VERSION 5.7 ;
BUSBITCHARS "[]" ;
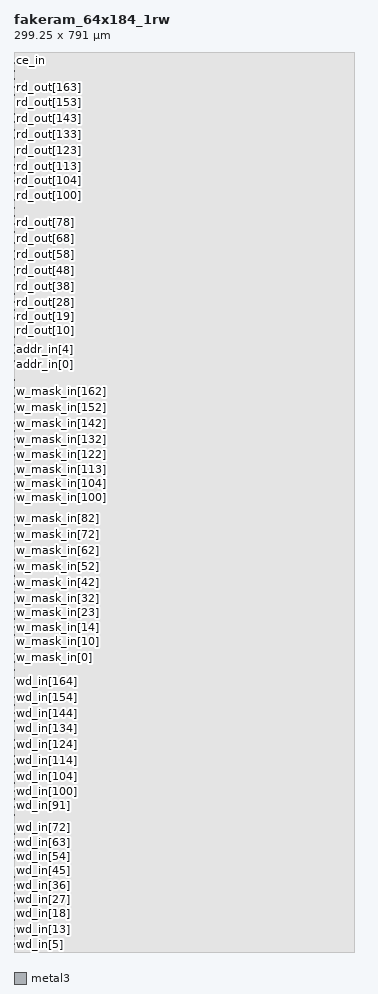
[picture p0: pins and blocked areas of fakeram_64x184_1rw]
MACRO fakeram_64x184_1rw
  FOREIGN fakeram_64x184_1rw 0 0 ;
  SYMMETRY X Y R90 ;
  SIZE 299.250 BY 791.000 ;
  CLASS BLOCK ;
  PIN wd_in[0]
    DIRECTION INPUT ;
    USE SIGNAL ;
    SHAPE ABUTMENT ;
    PORT
      LAYER metal3 ;
      RECT 0.000 1.400 0.140 1.540 ;
    END
  END wd_in[0]
  PIN wd_in[1]
    DIRECTION INPUT ;
    USE SIGNAL ;
    SHAPE ABUTMENT ;
    PORT
      LAYER metal3 ;
      RECT 0.000 2.800 0.140 2.940 ;
    END
  END wd_in[1]
  PIN wd_in[2]
    DIRECTION INPUT ;
    USE SIGNAL ;
    SHAPE ABUTMENT ;
    PORT
      LAYER metal3 ;
      RECT 0.000 4.200 0.140 4.340 ;
    END
  END wd_in[2]
  PIN wd_in[3]
    DIRECTION INPUT ;
    USE SIGNAL ;
    SHAPE ABUTMENT ;
    PORT
      LAYER metal3 ;
      RECT 0.000 5.600 0.140 5.740 ;
    END
  END wd_in[3]
  PIN wd_in[4]
    DIRECTION INPUT ;
    USE SIGNAL ;
    SHAPE ABUTMENT ;
    PORT
      LAYER metal3 ;
      RECT 0.000 7.000 0.140 7.140 ;
    END
  END wd_in[4]
  PIN wd_in[5]
    DIRECTION INPUT ;
    USE SIGNAL ;
    SHAPE ABUTMENT ;
    PORT
      LAYER metal3 ;
      RECT 0.000 8.400 0.140 8.540 ;
    END
  END wd_in[5]
  PIN wd_in[6]
    DIRECTION INPUT ;
    USE SIGNAL ;
    SHAPE ABUTMENT ;
    PORT
      LAYER metal3 ;
      RECT 0.000 9.800 0.140 9.940 ;
    END
  END wd_in[6]
  PIN wd_in[7]
    DIRECTION INPUT ;
    USE SIGNAL ;
    SHAPE ABUTMENT ;
    PORT
      LAYER metal3 ;
      RECT 0.000 11.200 0.140 11.340 ;
    END
  END wd_in[7]
  PIN wd_in[8]
    DIRECTION INPUT ;
    USE SIGNAL ;
    SHAPE ABUTMENT ;
    PORT
      LAYER metal3 ;
      RECT 0.000 12.600 0.140 12.740 ;
    END
  END wd_in[8]
  PIN wd_in[9]
    DIRECTION INPUT ;
    USE SIGNAL ;
    SHAPE ABUTMENT ;
    PORT
      LAYER metal3 ;
      RECT 0.000 14.000 0.140 14.140 ;
    END
  END wd_in[9]
  PIN wd_in[10]
    DIRECTION INPUT ;
    USE SIGNAL ;
    SHAPE ABUTMENT ;
    PORT
      LAYER metal3 ;
      RECT 0.000 15.400 0.140 15.540 ;
    END
  END wd_in[10]
  PIN wd_in[11]
    DIRECTION INPUT ;
    USE SIGNAL ;
    SHAPE ABUTMENT ;
    PORT
      LAYER metal3 ;
      RECT 0.000 16.800 0.140 16.940 ;
    END
  END wd_in[11]
  PIN wd_in[12]
    DIRECTION INPUT ;
    USE SIGNAL ;
    SHAPE ABUTMENT ;
    PORT
      LAYER metal3 ;
      RECT 0.000 18.200 0.140 18.340 ;
    END
  END wd_in[12]
  PIN wd_in[13]
    DIRECTION INPUT ;
    USE SIGNAL ;
    SHAPE ABUTMENT ;
    PORT
      LAYER metal3 ;
      RECT 0.000 19.600 0.140 19.740 ;
    END
  END wd_in[13]
  PIN wd_in[14]
    DIRECTION INPUT ;
    USE SIGNAL ;
    SHAPE ABUTMENT ;
    PORT
      LAYER metal3 ;
      RECT 0.000 21.000 0.140 21.140 ;
    END
  END wd_in[14]
  PIN wd_in[15]
    DIRECTION INPUT ;
    USE SIGNAL ;
    SHAPE ABUTMENT ;
    PORT
      LAYER metal3 ;
      RECT 0.000 22.400 0.140 22.540 ;
    END
  END wd_in[15]
  PIN wd_in[16]
    DIRECTION INPUT ;
    USE SIGNAL ;
    SHAPE ABUTMENT ;
    PORT
      LAYER metal3 ;
      RECT 0.000 23.800 0.140 23.940 ;
    END
  END wd_in[16]
  PIN wd_in[17]
    DIRECTION INPUT ;
    USE SIGNAL ;
    SHAPE ABUTMENT ;
    PORT
      LAYER metal3 ;
      RECT 0.000 25.200 0.140 25.340 ;
    END
  END wd_in[17]
  PIN wd_in[18]
    DIRECTION INPUT ;
    USE SIGNAL ;
    SHAPE ABUTMENT ;
    PORT
      LAYER metal3 ;
      RECT 0.000 26.600 0.140 26.740 ;
    END
  END wd_in[18]
  PIN wd_in[19]
    DIRECTION INPUT ;
    USE SIGNAL ;
    SHAPE ABUTMENT ;
    PORT
      LAYER metal3 ;
      RECT 0.000 28.000 0.140 28.140 ;
    END
  END wd_in[19]
  PIN wd_in[20]
    DIRECTION INPUT ;
    USE SIGNAL ;
    SHAPE ABUTMENT ;
    PORT
      LAYER metal3 ;
      RECT 0.000 29.400 0.140 29.540 ;
    END
  END wd_in[20]
  PIN wd_in[21]
    DIRECTION INPUT ;
    USE SIGNAL ;
    SHAPE ABUTMENT ;
    PORT
      LAYER metal3 ;
      RECT 0.000 30.800 0.140 30.940 ;
    END
  END wd_in[21]
  PIN wd_in[22]
    DIRECTION INPUT ;
    USE SIGNAL ;
    SHAPE ABUTMENT ;
    PORT
      LAYER metal3 ;
      RECT 0.000 32.200 0.140 32.340 ;
    END
  END wd_in[22]
  PIN wd_in[23]
    DIRECTION INPUT ;
    USE SIGNAL ;
    SHAPE ABUTMENT ;
    PORT
      LAYER metal3 ;
      RECT 0.000 33.600 0.140 33.740 ;
    END
  END wd_in[23]
  PIN wd_in[24]
    DIRECTION INPUT ;
    USE SIGNAL ;
    SHAPE ABUTMENT ;
    PORT
      LAYER metal3 ;
      RECT 0.000 35.000 0.140 35.140 ;
    END
  END wd_in[24]
  PIN wd_in[25]
    DIRECTION INPUT ;
    USE SIGNAL ;
    SHAPE ABUTMENT ;
    PORT
      LAYER metal3 ;
      RECT 0.000 36.400 0.140 36.540 ;
    END
  END wd_in[25]
  PIN wd_in[26]
    DIRECTION INPUT ;
    USE SIGNAL ;
    SHAPE ABUTMENT ;
    PORT
      LAYER metal3 ;
      RECT 0.000 37.800 0.140 37.940 ;
    END
  END wd_in[26]
  PIN wd_in[27]
    DIRECTION INPUT ;
    USE SIGNAL ;
    SHAPE ABUTMENT ;
    PORT
      LAYER metal3 ;
      RECT 0.000 39.200 0.140 39.340 ;
    END
  END wd_in[27]
  PIN wd_in[28]
    DIRECTION INPUT ;
    USE SIGNAL ;
    SHAPE ABUTMENT ;
    PORT
      LAYER metal3 ;
      RECT 0.000 40.600 0.140 40.740 ;
    END
  END wd_in[28]
  PIN wd_in[29]
    DIRECTION INPUT ;
    USE SIGNAL ;
    SHAPE ABUTMENT ;
    PORT
      LAYER metal3 ;
      RECT 0.000 42.000 0.140 42.140 ;
    END
  END wd_in[29]
  PIN wd_in[30]
    DIRECTION INPUT ;
    USE SIGNAL ;
    SHAPE ABUTMENT ;
    PORT
      LAYER metal3 ;
      RECT 0.000 43.400 0.140 43.540 ;
    END
  END wd_in[30]
  PIN wd_in[31]
    DIRECTION INPUT ;
    USE SIGNAL ;
    SHAPE ABUTMENT ;
    PORT
      LAYER metal3 ;
      RECT 0.000 44.800 0.140 44.940 ;
    END
  END wd_in[31]
  PIN wd_in[32]
    DIRECTION INPUT ;
    USE SIGNAL ;
    SHAPE ABUTMENT ;
    PORT
      LAYER metal3 ;
      RECT 0.000 46.200 0.140 46.340 ;
    END
  END wd_in[32]
  PIN wd_in[33]
    DIRECTION INPUT ;
    USE SIGNAL ;
    SHAPE ABUTMENT ;
    PORT
      LAYER metal3 ;
      RECT 0.000 47.600 0.140 47.740 ;
    END
  END wd_in[33]
  PIN wd_in[34]
    DIRECTION INPUT ;
    USE SIGNAL ;
    SHAPE ABUTMENT ;
    PORT
      LAYER metal3 ;
      RECT 0.000 49.000 0.140 49.140 ;
    END
  END wd_in[34]
  PIN wd_in[35]
    DIRECTION INPUT ;
    USE SIGNAL ;
    SHAPE ABUTMENT ;
    PORT
      LAYER metal3 ;
      RECT 0.000 50.400 0.140 50.540 ;
    END
  END wd_in[35]
  PIN wd_in[36]
    DIRECTION INPUT ;
    USE SIGNAL ;
    SHAPE ABUTMENT ;
    PORT
      LAYER metal3 ;
      RECT 0.000 51.800 0.140 51.940 ;
    END
  END wd_in[36]
  PIN wd_in[37]
    DIRECTION INPUT ;
    USE SIGNAL ;
    SHAPE ABUTMENT ;
    PORT
      LAYER metal3 ;
      RECT 0.000 53.200 0.140 53.340 ;
    END
  END wd_in[37]
  PIN wd_in[38]
    DIRECTION INPUT ;
    USE SIGNAL ;
    SHAPE ABUTMENT ;
    PORT
      LAYER metal3 ;
      RECT 0.000 54.600 0.140 54.740 ;
    END
  END wd_in[38]
  PIN wd_in[39]
    DIRECTION INPUT ;
    USE SIGNAL ;
    SHAPE ABUTMENT ;
    PORT
      LAYER metal3 ;
      RECT 0.000 56.000 0.140 56.140 ;
    END
  END wd_in[39]
  PIN wd_in[40]
    DIRECTION INPUT ;
    USE SIGNAL ;
    SHAPE ABUTMENT ;
    PORT
      LAYER metal3 ;
      RECT 0.000 57.400 0.140 57.540 ;
    END
  END wd_in[40]
  PIN wd_in[41]
    DIRECTION INPUT ;
    USE SIGNAL ;
    SHAPE ABUTMENT ;
    PORT
      LAYER metal3 ;
      RECT 0.000 58.800 0.140 58.940 ;
    END
  END wd_in[41]
  PIN wd_in[42]
    DIRECTION INPUT ;
    USE SIGNAL ;
    SHAPE ABUTMENT ;
    PORT
      LAYER metal3 ;
      RECT 0.000 60.200 0.140 60.340 ;
    END
  END wd_in[42]
  PIN wd_in[43]
    DIRECTION INPUT ;
    USE SIGNAL ;
    SHAPE ABUTMENT ;
    PORT
      LAYER metal3 ;
      RECT 0.000 61.600 0.140 61.740 ;
    END
  END wd_in[43]
  PIN wd_in[44]
    DIRECTION INPUT ;
    USE SIGNAL ;
    SHAPE ABUTMENT ;
    PORT
      LAYER metal3 ;
      RECT 0.000 63.000 0.140 63.140 ;
    END
  END wd_in[44]
  PIN wd_in[45]
    DIRECTION INPUT ;
    USE SIGNAL ;
    SHAPE ABUTMENT ;
    PORT
      LAYER metal3 ;
      RECT 0.000 64.400 0.140 64.540 ;
    END
  END wd_in[45]
  PIN wd_in[46]
    DIRECTION INPUT ;
    USE SIGNAL ;
    SHAPE ABUTMENT ;
    PORT
      LAYER metal3 ;
      RECT 0.000 65.800 0.140 65.940 ;
    END
  END wd_in[46]
  PIN wd_in[47]
    DIRECTION INPUT ;
    USE SIGNAL ;
    SHAPE ABUTMENT ;
    PORT
      LAYER metal3 ;
      RECT 0.000 67.200 0.140 67.340 ;
    END
  END wd_in[47]
  PIN wd_in[48]
    DIRECTION INPUT ;
    USE SIGNAL ;
    SHAPE ABUTMENT ;
    PORT
      LAYER metal3 ;
      RECT 0.000 68.600 0.140 68.740 ;
    END
  END wd_in[48]
  PIN wd_in[49]
    DIRECTION INPUT ;
    USE SIGNAL ;
    SHAPE ABUTMENT ;
    PORT
      LAYER metal3 ;
      RECT 0.000 70.000 0.140 70.140 ;
    END
  END wd_in[49]
  PIN wd_in[50]
    DIRECTION INPUT ;
    USE SIGNAL ;
    SHAPE ABUTMENT ;
    PORT
      LAYER metal3 ;
      RECT 0.000 71.400 0.140 71.540 ;
    END
  END wd_in[50]
  PIN wd_in[51]
    DIRECTION INPUT ;
    USE SIGNAL ;
    SHAPE ABUTMENT ;
    PORT
      LAYER metal3 ;
      RECT 0.000 72.800 0.140 72.940 ;
    END
  END wd_in[51]
  PIN wd_in[52]
    DIRECTION INPUT ;
    USE SIGNAL ;
    SHAPE ABUTMENT ;
    PORT
      LAYER metal3 ;
      RECT 0.000 74.200 0.140 74.340 ;
    END
  END wd_in[52]
  PIN wd_in[53]
    DIRECTION INPUT ;
    USE SIGNAL ;
    SHAPE ABUTMENT ;
    PORT
      LAYER metal3 ;
      RECT 0.000 75.600 0.140 75.740 ;
    END
  END wd_in[53]
  PIN wd_in[54]
    DIRECTION INPUT ;
    USE SIGNAL ;
    SHAPE ABUTMENT ;
    PORT
      LAYER metal3 ;
      RECT 0.000 77.000 0.140 77.140 ;
    END
  END wd_in[54]
  PIN wd_in[55]
    DIRECTION INPUT ;
    USE SIGNAL ;
    SHAPE ABUTMENT ;
    PORT
      LAYER metal3 ;
      RECT 0.000 78.400 0.140 78.540 ;
    END
  END wd_in[55]
  PIN wd_in[56]
    DIRECTION INPUT ;
    USE SIGNAL ;
    SHAPE ABUTMENT ;
    PORT
      LAYER metal3 ;
      RECT 0.000 79.800 0.140 79.940 ;
    END
  END wd_in[56]
  PIN wd_in[57]
    DIRECTION INPUT ;
    USE SIGNAL ;
    SHAPE ABUTMENT ;
    PORT
      LAYER metal3 ;
      RECT 0.000 81.200 0.140 81.340 ;
    END
  END wd_in[57]
  PIN wd_in[58]
    DIRECTION INPUT ;
    USE SIGNAL ;
    SHAPE ABUTMENT ;
    PORT
      LAYER metal3 ;
      RECT 0.000 82.600 0.140 82.740 ;
    END
  END wd_in[58]
  PIN wd_in[59]
    DIRECTION INPUT ;
    USE SIGNAL ;
    SHAPE ABUTMENT ;
    PORT
      LAYER metal3 ;
      RECT 0.000 84.000 0.140 84.140 ;
    END
  END wd_in[59]
  PIN wd_in[60]
    DIRECTION INPUT ;
    USE SIGNAL ;
    SHAPE ABUTMENT ;
    PORT
      LAYER metal3 ;
      RECT 0.000 85.400 0.140 85.540 ;
    END
  END wd_in[60]
  PIN wd_in[61]
    DIRECTION INPUT ;
    USE SIGNAL ;
    SHAPE ABUTMENT ;
    PORT
      LAYER metal3 ;
      RECT 0.000 86.800 0.140 86.940 ;
    END
  END wd_in[61]
  PIN wd_in[62]
    DIRECTION INPUT ;
    USE SIGNAL ;
    SHAPE ABUTMENT ;
    PORT
      LAYER metal3 ;
      RECT 0.000 88.200 0.140 88.340 ;
    END
  END wd_in[62]
  PIN wd_in[63]
    DIRECTION INPUT ;
    USE SIGNAL ;
    SHAPE ABUTMENT ;
    PORT
      LAYER metal3 ;
      RECT 0.000 89.600 0.140 89.740 ;
    END
  END wd_in[63]
  PIN wd_in[64]
    DIRECTION INPUT ;
    USE SIGNAL ;
    SHAPE ABUTMENT ;
    PORT
      LAYER metal3 ;
      RECT 0.000 91.000 0.140 91.140 ;
    END
  END wd_in[64]
  PIN wd_in[65]
    DIRECTION INPUT ;
    USE SIGNAL ;
    SHAPE ABUTMENT ;
    PORT
      LAYER metal3 ;
      RECT 0.000 92.400 0.140 92.540 ;
    END
  END wd_in[65]
  PIN wd_in[66]
    DIRECTION INPUT ;
    USE SIGNAL ;
    SHAPE ABUTMENT ;
    PORT
      LAYER metal3 ;
      RECT 0.000 93.800 0.140 93.940 ;
    END
  END wd_in[66]
  PIN wd_in[67]
    DIRECTION INPUT ;
    USE SIGNAL ;
    SHAPE ABUTMENT ;
    PORT
      LAYER metal3 ;
      RECT 0.000 95.200 0.140 95.340 ;
    END
  END wd_in[67]
  PIN wd_in[68]
    DIRECTION INPUT ;
    USE SIGNAL ;
    SHAPE ABUTMENT ;
    PORT
      LAYER metal3 ;
      RECT 0.000 96.600 0.140 96.740 ;
    END
  END wd_in[68]
  PIN wd_in[69]
    DIRECTION INPUT ;
    USE SIGNAL ;
    SHAPE ABUTMENT ;
    PORT
      LAYER metal3 ;
      RECT 0.000 98.000 0.140 98.140 ;
    END
  END wd_in[69]
  PIN wd_in[70]
    DIRECTION INPUT ;
    USE SIGNAL ;
    SHAPE ABUTMENT ;
    PORT
      LAYER metal3 ;
      RECT 0.000 99.400 0.140 99.540 ;
    END
  END wd_in[70]
  PIN wd_in[71]
    DIRECTION INPUT ;
    USE SIGNAL ;
    SHAPE ABUTMENT ;
    PORT
      LAYER metal3 ;
      RECT 0.000 100.800 0.140 100.940 ;
    END
  END wd_in[71]
  PIN wd_in[72]
    DIRECTION INPUT ;
    USE SIGNAL ;
    SHAPE ABUTMENT ;
    PORT
      LAYER metal3 ;
      RECT 0.000 102.200 0.140 102.340 ;
    END
  END wd_in[72]
  PIN wd_in[73]
    DIRECTION INPUT ;
    USE SIGNAL ;
    SHAPE ABUTMENT ;
    PORT
      LAYER metal3 ;
      RECT 0.000 103.600 0.140 103.740 ;
    END
  END wd_in[73]
  PIN wd_in[74]
    DIRECTION INPUT ;
    USE SIGNAL ;
    SHAPE ABUTMENT ;
    PORT
      LAYER metal3 ;
      RECT 0.000 105.000 0.140 105.140 ;
    END
  END wd_in[74]
  PIN wd_in[75]
    DIRECTION INPUT ;
    USE SIGNAL ;
    SHAPE ABUTMENT ;
    PORT
      LAYER metal3 ;
      RECT 0.000 106.400 0.140 106.540 ;
    END
  END wd_in[75]
  PIN wd_in[76]
    DIRECTION INPUT ;
    USE SIGNAL ;
    SHAPE ABUTMENT ;
    PORT
      LAYER metal3 ;
      RECT 0.000 107.800 0.140 107.940 ;
    END
  END wd_in[76]
  PIN wd_in[77]
    DIRECTION INPUT ;
    USE SIGNAL ;
    SHAPE ABUTMENT ;
    PORT
      LAYER metal3 ;
      RECT 0.000 109.200 0.140 109.340 ;
    END
  END wd_in[77]
  PIN wd_in[78]
    DIRECTION INPUT ;
    USE SIGNAL ;
    SHAPE ABUTMENT ;
    PORT
      LAYER metal3 ;
      RECT 0.000 110.600 0.140 110.740 ;
    END
  END wd_in[78]
  PIN wd_in[79]
    DIRECTION INPUT ;
    USE SIGNAL ;
    SHAPE ABUTMENT ;
    PORT
      LAYER metal3 ;
      RECT 0.000 112.000 0.140 112.140 ;
    END
  END wd_in[79]
  PIN wd_in[80]
    DIRECTION INPUT ;
    USE SIGNAL ;
    SHAPE ABUTMENT ;
    PORT
      LAYER metal3 ;
      RECT 0.000 113.400 0.140 113.540 ;
    END
  END wd_in[80]
  PIN wd_in[81]
    DIRECTION INPUT ;
    USE SIGNAL ;
    SHAPE ABUTMENT ;
    PORT
      LAYER metal3 ;
      RECT 0.000 114.800 0.140 114.940 ;
    END
  END wd_in[81]
  PIN wd_in[82]
    DIRECTION INPUT ;
    USE SIGNAL ;
    SHAPE ABUTMENT ;
    PORT
      LAYER metal3 ;
      RECT 0.000 116.200 0.140 116.340 ;
    END
  END wd_in[82]
  PIN wd_in[83]
    DIRECTION INPUT ;
    USE SIGNAL ;
    SHAPE ABUTMENT ;
    PORT
      LAYER metal3 ;
      RECT 0.000 117.600 0.140 117.740 ;
    END
  END wd_in[83]
  PIN wd_in[84]
    DIRECTION INPUT ;
    USE SIGNAL ;
    SHAPE ABUTMENT ;
    PORT
      LAYER metal3 ;
      RECT 0.000 119.000 0.140 119.140 ;
    END
  END wd_in[84]
  PIN wd_in[85]
    DIRECTION INPUT ;
    USE SIGNAL ;
    SHAPE ABUTMENT ;
    PORT
      LAYER metal3 ;
      RECT 0.000 120.400 0.140 120.540 ;
    END
  END wd_in[85]
  PIN wd_in[86]
    DIRECTION INPUT ;
    USE SIGNAL ;
    SHAPE ABUTMENT ;
    PORT
      LAYER metal3 ;
      RECT 0.000 121.800 0.140 121.940 ;
    END
  END wd_in[86]
  PIN wd_in[87]
    DIRECTION INPUT ;
    USE SIGNAL ;
    SHAPE ABUTMENT ;
    PORT
      LAYER metal3 ;
      RECT 0.000 123.200 0.140 123.340 ;
    END
  END wd_in[87]
  PIN wd_in[88]
    DIRECTION INPUT ;
    USE SIGNAL ;
    SHAPE ABUTMENT ;
    PORT
      LAYER metal3 ;
      RECT 0.000 124.600 0.140 124.740 ;
    END
  END wd_in[88]
  PIN wd_in[89]
    DIRECTION INPUT ;
    USE SIGNAL ;
    SHAPE ABUTMENT ;
    PORT
      LAYER metal3 ;
      RECT 0.000 126.000 0.140 126.140 ;
    END
  END wd_in[89]
  PIN wd_in[90]
    DIRECTION INPUT ;
    USE SIGNAL ;
    SHAPE ABUTMENT ;
    PORT
      LAYER metal3 ;
      RECT 0.000 127.400 0.140 127.540 ;
    END
  END wd_in[90]
  PIN wd_in[91]
    DIRECTION INPUT ;
    USE SIGNAL ;
    SHAPE ABUTMENT ;
    PORT
      LAYER metal3 ;
      RECT 0.000 128.800 0.140 128.940 ;
    END
  END wd_in[91]
  PIN wd_in[92]
    DIRECTION INPUT ;
    USE SIGNAL ;
    SHAPE ABUTMENT ;
    PORT
      LAYER metal3 ;
      RECT 0.000 130.200 0.140 130.340 ;
    END
  END wd_in[92]
  PIN wd_in[93]
    DIRECTION INPUT ;
    USE SIGNAL ;
    SHAPE ABUTMENT ;
    PORT
      LAYER metal3 ;
      RECT 0.000 131.600 0.140 131.740 ;
    END
  END wd_in[93]
  PIN wd_in[94]
    DIRECTION INPUT ;
    USE SIGNAL ;
    SHAPE ABUTMENT ;
    PORT
      LAYER metal3 ;
      RECT 0.000 133.000 0.140 133.140 ;
    END
  END wd_in[94]
  PIN wd_in[95]
    DIRECTION INPUT ;
    USE SIGNAL ;
    SHAPE ABUTMENT ;
    PORT
      LAYER metal3 ;
      RECT 0.000 134.400 0.140 134.540 ;
    END
  END wd_in[95]
  PIN wd_in[96]
    DIRECTION INPUT ;
    USE SIGNAL ;
    SHAPE ABUTMENT ;
    PORT
      LAYER metal3 ;
      RECT 0.000 135.800 0.140 135.940 ;
    END
  END wd_in[96]
  PIN wd_in[97]
    DIRECTION INPUT ;
    USE SIGNAL ;
    SHAPE ABUTMENT ;
    PORT
      LAYER metal3 ;
      RECT 0.000 137.200 0.140 137.340 ;
    END
  END wd_in[97]
  PIN wd_in[98]
    DIRECTION INPUT ;
    USE SIGNAL ;
    SHAPE ABUTMENT ;
    PORT
      LAYER metal3 ;
      RECT 0.000 138.600 0.140 138.740 ;
    END
  END wd_in[98]
  PIN wd_in[99]
    DIRECTION INPUT ;
    USE SIGNAL ;
    SHAPE ABUTMENT ;
    PORT
      LAYER metal3 ;
      RECT 0.000 140.000 0.140 140.140 ;
    END
  END wd_in[99]
  PIN wd_in[100]
    DIRECTION INPUT ;
    USE SIGNAL ;
    SHAPE ABUTMENT ;
    PORT
      LAYER metal3 ;
      RECT 0.000 141.400 0.140 141.540 ;
    END
  END wd_in[100]
  PIN wd_in[101]
    DIRECTION INPUT ;
    USE SIGNAL ;
    SHAPE ABUTMENT ;
    PORT
      LAYER metal3 ;
      RECT 0.000 142.800 0.140 142.940 ;
    END
  END wd_in[101]
  PIN wd_in[102]
    DIRECTION INPUT ;
    USE SIGNAL ;
    SHAPE ABUTMENT ;
    PORT
      LAYER metal3 ;
      RECT 0.000 144.200 0.140 144.340 ;
    END
  END wd_in[102]
  PIN wd_in[103]
    DIRECTION INPUT ;
    USE SIGNAL ;
    SHAPE ABUTMENT ;
    PORT
      LAYER metal3 ;
      RECT 0.000 145.600 0.140 145.740 ;
    END
  END wd_in[103]
  PIN wd_in[104]
    DIRECTION INPUT ;
    USE SIGNAL ;
    SHAPE ABUTMENT ;
    PORT
      LAYER metal3 ;
      RECT 0.000 147.000 0.140 147.140 ;
    END
  END wd_in[104]
  PIN wd_in[105]
    DIRECTION INPUT ;
    USE SIGNAL ;
    SHAPE ABUTMENT ;
    PORT
      LAYER metal3 ;
      RECT 0.000 148.400 0.140 148.540 ;
    END
  END wd_in[105]
  PIN wd_in[106]
    DIRECTION INPUT ;
    USE SIGNAL ;
    SHAPE ABUTMENT ;
    PORT
      LAYER metal3 ;
      RECT 0.000 149.800 0.140 149.940 ;
    END
  END wd_in[106]
  PIN wd_in[107]
    DIRECTION INPUT ;
    USE SIGNAL ;
    SHAPE ABUTMENT ;
    PORT
      LAYER metal3 ;
      RECT 0.000 151.200 0.140 151.340 ;
    END
  END wd_in[107]
  PIN wd_in[108]
    DIRECTION INPUT ;
    USE SIGNAL ;
    SHAPE ABUTMENT ;
    PORT
      LAYER metal3 ;
      RECT 0.000 152.600 0.140 152.740 ;
    END
  END wd_in[108]
  PIN wd_in[109]
    DIRECTION INPUT ;
    USE SIGNAL ;
    SHAPE ABUTMENT ;
    PORT
      LAYER metal3 ;
      RECT 0.000 154.000 0.140 154.140 ;
    END
  END wd_in[109]
  PIN wd_in[110]
    DIRECTION INPUT ;
    USE SIGNAL ;
    SHAPE ABUTMENT ;
    PORT
      LAYER metal3 ;
      RECT 0.000 155.400 0.140 155.540 ;
    END
  END wd_in[110]
  PIN wd_in[111]
    DIRECTION INPUT ;
    USE SIGNAL ;
    SHAPE ABUTMENT ;
    PORT
      LAYER metal3 ;
      RECT 0.000 156.800 0.140 156.940 ;
    END
  END wd_in[111]
  PIN wd_in[112]
    DIRECTION INPUT ;
    USE SIGNAL ;
    SHAPE ABUTMENT ;
    PORT
      LAYER metal3 ;
      RECT 0.000 158.200 0.140 158.340 ;
    END
  END wd_in[112]
  PIN wd_in[113]
    DIRECTION INPUT ;
    USE SIGNAL ;
    SHAPE ABUTMENT ;
    PORT
      LAYER metal3 ;
      RECT 0.000 159.600 0.140 159.740 ;
    END
  END wd_in[113]
  PIN wd_in[114]
    DIRECTION INPUT ;
    USE SIGNAL ;
    SHAPE ABUTMENT ;
    PORT
      LAYER metal3 ;
      RECT 0.000 161.000 0.140 161.140 ;
    END
  END wd_in[114]
  PIN wd_in[115]
    DIRECTION INPUT ;
    USE SIGNAL ;
    SHAPE ABUTMENT ;
    PORT
      LAYER metal3 ;
      RECT 0.000 162.400 0.140 162.540 ;
    END
  END wd_in[115]
  PIN wd_in[116]
    DIRECTION INPUT ;
    USE SIGNAL ;
    SHAPE ABUTMENT ;
    PORT
      LAYER metal3 ;
      RECT 0.000 163.800 0.140 163.940 ;
    END
  END wd_in[116]
  PIN wd_in[117]
    DIRECTION INPUT ;
    USE SIGNAL ;
    SHAPE ABUTMENT ;
    PORT
      LAYER metal3 ;
      RECT 0.000 165.200 0.140 165.340 ;
    END
  END wd_in[117]
  PIN wd_in[118]
    DIRECTION INPUT ;
    USE SIGNAL ;
    SHAPE ABUTMENT ;
    PORT
      LAYER metal3 ;
      RECT 0.000 166.600 0.140 166.740 ;
    END
  END wd_in[118]
  PIN wd_in[119]
    DIRECTION INPUT ;
    USE SIGNAL ;
    SHAPE ABUTMENT ;
    PORT
      LAYER metal3 ;
      RECT 0.000 168.000 0.140 168.140 ;
    END
  END wd_in[119]
  PIN wd_in[120]
    DIRECTION INPUT ;
    USE SIGNAL ;
    SHAPE ABUTMENT ;
    PORT
      LAYER metal3 ;
      RECT 0.000 169.400 0.140 169.540 ;
    END
  END wd_in[120]
  PIN wd_in[121]
    DIRECTION INPUT ;
    USE SIGNAL ;
    SHAPE ABUTMENT ;
    PORT
      LAYER metal3 ;
      RECT 0.000 170.800 0.140 170.940 ;
    END
  END wd_in[121]
  PIN wd_in[122]
    DIRECTION INPUT ;
    USE SIGNAL ;
    SHAPE ABUTMENT ;
    PORT
      LAYER metal3 ;
      RECT 0.000 172.200 0.140 172.340 ;
    END
  END wd_in[122]
  PIN wd_in[123]
    DIRECTION INPUT ;
    USE SIGNAL ;
    SHAPE ABUTMENT ;
    PORT
      LAYER metal3 ;
      RECT 0.000 173.600 0.140 173.740 ;
    END
  END wd_in[123]
  PIN wd_in[124]
    DIRECTION INPUT ;
    USE SIGNAL ;
    SHAPE ABUTMENT ;
    PORT
      LAYER metal3 ;
      RECT 0.000 175.000 0.140 175.140 ;
    END
  END wd_in[124]
  PIN wd_in[125]
    DIRECTION INPUT ;
    USE SIGNAL ;
    SHAPE ABUTMENT ;
    PORT
      LAYER metal3 ;
      RECT 0.000 176.400 0.140 176.540 ;
    END
  END wd_in[125]
  PIN wd_in[126]
    DIRECTION INPUT ;
    USE SIGNAL ;
    SHAPE ABUTMENT ;
    PORT
      LAYER metal3 ;
      RECT 0.000 177.800 0.140 177.940 ;
    END
  END wd_in[126]
  PIN wd_in[127]
    DIRECTION INPUT ;
    USE SIGNAL ;
    SHAPE ABUTMENT ;
    PORT
      LAYER metal3 ;
      RECT 0.000 179.200 0.140 179.340 ;
    END
  END wd_in[127]
  PIN wd_in[128]
    DIRECTION INPUT ;
    USE SIGNAL ;
    SHAPE ABUTMENT ;
    PORT
      LAYER metal3 ;
      RECT 0.000 180.600 0.140 180.740 ;
    END
  END wd_in[128]
  PIN wd_in[129]
    DIRECTION INPUT ;
    USE SIGNAL ;
    SHAPE ABUTMENT ;
    PORT
      LAYER metal3 ;
      RECT 0.000 182.000 0.140 182.140 ;
    END
  END wd_in[129]
  PIN wd_in[130]
    DIRECTION INPUT ;
    USE SIGNAL ;
    SHAPE ABUTMENT ;
    PORT
      LAYER metal3 ;
      RECT 0.000 183.400 0.140 183.540 ;
    END
  END wd_in[130]
  PIN wd_in[131]
    DIRECTION INPUT ;
    USE SIGNAL ;
    SHAPE ABUTMENT ;
    PORT
      LAYER metal3 ;
      RECT 0.000 184.800 0.140 184.940 ;
    END
  END wd_in[131]
  PIN wd_in[132]
    DIRECTION INPUT ;
    USE SIGNAL ;
    SHAPE ABUTMENT ;
    PORT
      LAYER metal3 ;
      RECT 0.000 186.200 0.140 186.340 ;
    END
  END wd_in[132]
  PIN wd_in[133]
    DIRECTION INPUT ;
    USE SIGNAL ;
    SHAPE ABUTMENT ;
    PORT
      LAYER metal3 ;
      RECT 0.000 187.600 0.140 187.740 ;
    END
  END wd_in[133]
  PIN wd_in[134]
    DIRECTION INPUT ;
    USE SIGNAL ;
    SHAPE ABUTMENT ;
    PORT
      LAYER metal3 ;
      RECT 0.000 189.000 0.140 189.140 ;
    END
  END wd_in[134]
  PIN wd_in[135]
    DIRECTION INPUT ;
    USE SIGNAL ;
    SHAPE ABUTMENT ;
    PORT
      LAYER metal3 ;
      RECT 0.000 190.400 0.140 190.540 ;
    END
  END wd_in[135]
  PIN wd_in[136]
    DIRECTION INPUT ;
    USE SIGNAL ;
    SHAPE ABUTMENT ;
    PORT
      LAYER metal3 ;
      RECT 0.000 191.800 0.140 191.940 ;
    END
  END wd_in[136]
  PIN wd_in[137]
    DIRECTION INPUT ;
    USE SIGNAL ;
    SHAPE ABUTMENT ;
    PORT
      LAYER metal3 ;
      RECT 0.000 193.200 0.140 193.340 ;
    END
  END wd_in[137]
  PIN wd_in[138]
    DIRECTION INPUT ;
    USE SIGNAL ;
    SHAPE ABUTMENT ;
    PORT
      LAYER metal3 ;
      RECT 0.000 194.600 0.140 194.740 ;
    END
  END wd_in[138]
  PIN wd_in[139]
    DIRECTION INPUT ;
    USE SIGNAL ;
    SHAPE ABUTMENT ;
    PORT
      LAYER metal3 ;
      RECT 0.000 196.000 0.140 196.140 ;
    END
  END wd_in[139]
  PIN wd_in[140]
    DIRECTION INPUT ;
    USE SIGNAL ;
    SHAPE ABUTMENT ;
    PORT
      LAYER metal3 ;
      RECT 0.000 197.400 0.140 197.540 ;
    END
  END wd_in[140]
  PIN wd_in[141]
    DIRECTION INPUT ;
    USE SIGNAL ;
    SHAPE ABUTMENT ;
    PORT
      LAYER metal3 ;
      RECT 0.000 198.800 0.140 198.940 ;
    END
  END wd_in[141]
  PIN wd_in[142]
    DIRECTION INPUT ;
    USE SIGNAL ;
    SHAPE ABUTMENT ;
    PORT
      LAYER metal3 ;
      RECT 0.000 200.200 0.140 200.340 ;
    END
  END wd_in[142]
  PIN wd_in[143]
    DIRECTION INPUT ;
    USE SIGNAL ;
    SHAPE ABUTMENT ;
    PORT
      LAYER metal3 ;
      RECT 0.000 201.600 0.140 201.740 ;
    END
  END wd_in[143]
  PIN wd_in[144]
    DIRECTION INPUT ;
    USE SIGNAL ;
    SHAPE ABUTMENT ;
    PORT
      LAYER metal3 ;
      RECT 0.000 203.000 0.140 203.140 ;
    END
  END wd_in[144]
  PIN wd_in[145]
    DIRECTION INPUT ;
    USE SIGNAL ;
    SHAPE ABUTMENT ;
    PORT
      LAYER metal3 ;
      RECT 0.000 204.400 0.140 204.540 ;
    END
  END wd_in[145]
  PIN wd_in[146]
    DIRECTION INPUT ;
    USE SIGNAL ;
    SHAPE ABUTMENT ;
    PORT
      LAYER metal3 ;
      RECT 0.000 205.800 0.140 205.940 ;
    END
  END wd_in[146]
  PIN wd_in[147]
    DIRECTION INPUT ;
    USE SIGNAL ;
    SHAPE ABUTMENT ;
    PORT
      LAYER metal3 ;
      RECT 0.000 207.200 0.140 207.340 ;
    END
  END wd_in[147]
  PIN wd_in[148]
    DIRECTION INPUT ;
    USE SIGNAL ;
    SHAPE ABUTMENT ;
    PORT
      LAYER metal3 ;
      RECT 0.000 208.600 0.140 208.740 ;
    END
  END wd_in[148]
  PIN wd_in[149]
    DIRECTION INPUT ;
    USE SIGNAL ;
    SHAPE ABUTMENT ;
    PORT
      LAYER metal3 ;
      RECT 0.000 210.000 0.140 210.140 ;
    END
  END wd_in[149]
  PIN wd_in[150]
    DIRECTION INPUT ;
    USE SIGNAL ;
    SHAPE ABUTMENT ;
    PORT
      LAYER metal3 ;
      RECT 0.000 211.400 0.140 211.540 ;
    END
  END wd_in[150]
  PIN wd_in[151]
    DIRECTION INPUT ;
    USE SIGNAL ;
    SHAPE ABUTMENT ;
    PORT
      LAYER metal3 ;
      RECT 0.000 212.800 0.140 212.940 ;
    END
  END wd_in[151]
  PIN wd_in[152]
    DIRECTION INPUT ;
    USE SIGNAL ;
    SHAPE ABUTMENT ;
    PORT
      LAYER metal3 ;
      RECT 0.000 214.200 0.140 214.340 ;
    END
  END wd_in[152]
  PIN wd_in[153]
    DIRECTION INPUT ;
    USE SIGNAL ;
    SHAPE ABUTMENT ;
    PORT
      LAYER metal3 ;
      RECT 0.000 215.600 0.140 215.740 ;
    END
  END wd_in[153]
  PIN wd_in[154]
    DIRECTION INPUT ;
    USE SIGNAL ;
    SHAPE ABUTMENT ;
    PORT
      LAYER metal3 ;
      RECT 0.000 217.000 0.140 217.140 ;
    END
  END wd_in[154]
  PIN wd_in[155]
    DIRECTION INPUT ;
    USE SIGNAL ;
    SHAPE ABUTMENT ;
    PORT
      LAYER metal3 ;
      RECT 0.000 218.400 0.140 218.540 ;
    END
  END wd_in[155]
  PIN wd_in[156]
    DIRECTION INPUT ;
    USE SIGNAL ;
    SHAPE ABUTMENT ;
    PORT
      LAYER metal3 ;
      RECT 0.000 219.800 0.140 219.940 ;
    END
  END wd_in[156]
  PIN wd_in[157]
    DIRECTION INPUT ;
    USE SIGNAL ;
    SHAPE ABUTMENT ;
    PORT
      LAYER metal3 ;
      RECT 0.000 221.200 0.140 221.340 ;
    END
  END wd_in[157]
  PIN wd_in[158]
    DIRECTION INPUT ;
    USE SIGNAL ;
    SHAPE ABUTMENT ;
    PORT
      LAYER metal3 ;
      RECT 0.000 222.600 0.140 222.740 ;
    END
  END wd_in[158]
  PIN wd_in[159]
    DIRECTION INPUT ;
    USE SIGNAL ;
    SHAPE ABUTMENT ;
    PORT
      LAYER metal3 ;
      RECT 0.000 224.000 0.140 224.140 ;
    END
  END wd_in[159]
  PIN wd_in[160]
    DIRECTION INPUT ;
    USE SIGNAL ;
    SHAPE ABUTMENT ;
    PORT
      LAYER metal3 ;
      RECT 0.000 225.400 0.140 225.540 ;
    END
  END wd_in[160]
  PIN wd_in[161]
    DIRECTION INPUT ;
    USE SIGNAL ;
    SHAPE ABUTMENT ;
    PORT
      LAYER metal3 ;
      RECT 0.000 226.800 0.140 226.940 ;
    END
  END wd_in[161]
  PIN wd_in[162]
    DIRECTION INPUT ;
    USE SIGNAL ;
    SHAPE ABUTMENT ;
    PORT
      LAYER metal3 ;
      RECT 0.000 228.200 0.140 228.340 ;
    END
  END wd_in[162]
  PIN wd_in[163]
    DIRECTION INPUT ;
    USE SIGNAL ;
    SHAPE ABUTMENT ;
    PORT
      LAYER metal3 ;
      RECT 0.000 229.600 0.140 229.740 ;
    END
  END wd_in[163]
  PIN wd_in[164]
    DIRECTION INPUT ;
    USE SIGNAL ;
    SHAPE ABUTMENT ;
    PORT
      LAYER metal3 ;
      RECT 0.000 231.000 0.140 231.140 ;
    END
  END wd_in[164]
  PIN wd_in[165]
    DIRECTION INPUT ;
    USE SIGNAL ;
    SHAPE ABUTMENT ;
    PORT
      LAYER metal3 ;
      RECT 0.000 232.400 0.140 232.540 ;
    END
  END wd_in[165]
  PIN wd_in[166]
    DIRECTION INPUT ;
    USE SIGNAL ;
    SHAPE ABUTMENT ;
    PORT
      LAYER metal3 ;
      RECT 0.000 233.800 0.140 233.940 ;
    END
  END wd_in[166]
  PIN wd_in[167]
    DIRECTION INPUT ;
    USE SIGNAL ;
    SHAPE ABUTMENT ;
    PORT
      LAYER metal3 ;
      RECT 0.000 235.200 0.140 235.340 ;
    END
  END wd_in[167]
  PIN wd_in[168]
    DIRECTION INPUT ;
    USE SIGNAL ;
    SHAPE ABUTMENT ;
    PORT
      LAYER metal3 ;
      RECT 0.000 236.600 0.140 236.740 ;
    END
  END wd_in[168]
  PIN wd_in[169]
    DIRECTION INPUT ;
    USE SIGNAL ;
    SHAPE ABUTMENT ;
    PORT
      LAYER metal3 ;
      RECT 0.000 238.000 0.140 238.140 ;
    END
  END wd_in[169]
  PIN wd_in[170]
    DIRECTION INPUT ;
    USE SIGNAL ;
    SHAPE ABUTMENT ;
    PORT
      LAYER metal3 ;
      RECT 0.000 239.400 0.140 239.540 ;
    END
  END wd_in[170]
  PIN wd_in[171]
    DIRECTION INPUT ;
    USE SIGNAL ;
    SHAPE ABUTMENT ;
    PORT
      LAYER metal3 ;
      RECT 0.000 240.800 0.140 240.940 ;
    END
  END wd_in[171]
  PIN wd_in[172]
    DIRECTION INPUT ;
    USE SIGNAL ;
    SHAPE ABUTMENT ;
    PORT
      LAYER metal3 ;
      RECT 0.000 242.200 0.140 242.340 ;
    END
  END wd_in[172]
  PIN wd_in[173]
    DIRECTION INPUT ;
    USE SIGNAL ;
    SHAPE ABUTMENT ;
    PORT
      LAYER metal3 ;
      RECT 0.000 243.600 0.140 243.740 ;
    END
  END wd_in[173]
  PIN wd_in[174]
    DIRECTION INPUT ;
    USE SIGNAL ;
    SHAPE ABUTMENT ;
    PORT
      LAYER metal3 ;
      RECT 0.000 245.000 0.140 245.140 ;
    END
  END wd_in[174]
  PIN wd_in[175]
    DIRECTION INPUT ;
    USE SIGNAL ;
    SHAPE ABUTMENT ;
    PORT
      LAYER metal3 ;
      RECT 0.000 246.400 0.140 246.540 ;
    END
  END wd_in[175]
  PIN wd_in[176]
    DIRECTION INPUT ;
    USE SIGNAL ;
    SHAPE ABUTMENT ;
    PORT
      LAYER metal3 ;
      RECT 0.000 247.800 0.140 247.940 ;
    END
  END wd_in[176]
  PIN wd_in[177]
    DIRECTION INPUT ;
    USE SIGNAL ;
    SHAPE ABUTMENT ;
    PORT
      LAYER metal3 ;
      RECT 0.000 249.200 0.140 249.340 ;
    END
  END wd_in[177]
  PIN wd_in[178]
    DIRECTION INPUT ;
    USE SIGNAL ;
    SHAPE ABUTMENT ;
    PORT
      LAYER metal3 ;
      RECT 0.000 250.600 0.140 250.740 ;
    END
  END wd_in[178]
  PIN wd_in[179]
    DIRECTION INPUT ;
    USE SIGNAL ;
    SHAPE ABUTMENT ;
    PORT
      LAYER metal3 ;
      RECT 0.000 252.000 0.140 252.140 ;
    END
  END wd_in[179]
  PIN wd_in[180]
    DIRECTION INPUT ;
    USE SIGNAL ;
    SHAPE ABUTMENT ;
    PORT
      LAYER metal3 ;
      RECT 0.000 253.400 0.140 253.540 ;
    END
  END wd_in[180]
  PIN wd_in[181]
    DIRECTION INPUT ;
    USE SIGNAL ;
    SHAPE ABUTMENT ;
    PORT
      LAYER metal3 ;
      RECT 0.000 254.800 0.140 254.940 ;
    END
  END wd_in[181]
  PIN wd_in[182]
    DIRECTION INPUT ;
    USE SIGNAL ;
    SHAPE ABUTMENT ;
    PORT
      LAYER metal3 ;
      RECT 0.000 256.200 0.140 256.340 ;
    END
  END wd_in[182]
  PIN wd_in[183]
    DIRECTION INPUT ;
    USE SIGNAL ;
    SHAPE ABUTMENT ;
    PORT
      LAYER metal3 ;
      RECT 0.000 257.600 0.140 257.740 ;
    END
  END wd_in[183]
  PIN w_mask_in[0]
    DIRECTION INPUT ;
    USE SIGNAL ;
    SHAPE ABUTMENT ;
    PORT
      LAYER metal3 ;
      RECT 0.000 259.000 0.140 259.140 ;
    END
  END w_mask_in[0]
  PIN w_mask_in[1]
    DIRECTION INPUT ;
    USE SIGNAL ;
    SHAPE ABUTMENT ;
    PORT
      LAYER metal3 ;
      RECT 0.000 260.400 0.140 260.540 ;
    END
  END w_mask_in[1]
  PIN w_mask_in[2]
    DIRECTION INPUT ;
    USE SIGNAL ;
    SHAPE ABUTMENT ;
    PORT
      LAYER metal3 ;
      RECT 0.000 261.800 0.140 261.940 ;
    END
  END w_mask_in[2]
  PIN w_mask_in[3]
    DIRECTION INPUT ;
    USE SIGNAL ;
    SHAPE ABUTMENT ;
    PORT
      LAYER metal3 ;
      RECT 0.000 263.200 0.140 263.340 ;
    END
  END w_mask_in[3]
  PIN w_mask_in[4]
    DIRECTION INPUT ;
    USE SIGNAL ;
    SHAPE ABUTMENT ;
    PORT
      LAYER metal3 ;
      RECT 0.000 264.600 0.140 264.740 ;
    END
  END w_mask_in[4]
  PIN w_mask_in[5]
    DIRECTION INPUT ;
    USE SIGNAL ;
    SHAPE ABUTMENT ;
    PORT
      LAYER metal3 ;
      RECT 0.000 266.000 0.140 266.140 ;
    END
  END w_mask_in[5]
  PIN w_mask_in[6]
    DIRECTION INPUT ;
    USE SIGNAL ;
    SHAPE ABUTMENT ;
    PORT
      LAYER metal3 ;
      RECT 0.000 267.400 0.140 267.540 ;
    END
  END w_mask_in[6]
  PIN w_mask_in[7]
    DIRECTION INPUT ;
    USE SIGNAL ;
    SHAPE ABUTMENT ;
    PORT
      LAYER metal3 ;
      RECT 0.000 268.800 0.140 268.940 ;
    END
  END w_mask_in[7]
  PIN w_mask_in[8]
    DIRECTION INPUT ;
    USE SIGNAL ;
    SHAPE ABUTMENT ;
    PORT
      LAYER metal3 ;
      RECT 0.000 270.200 0.140 270.340 ;
    END
  END w_mask_in[8]
  PIN w_mask_in[9]
    DIRECTION INPUT ;
    USE SIGNAL ;
    SHAPE ABUTMENT ;
    PORT
      LAYER metal3 ;
      RECT 0.000 271.600 0.140 271.740 ;
    END
  END w_mask_in[9]
  PIN w_mask_in[10]
    DIRECTION INPUT ;
    USE SIGNAL ;
    SHAPE ABUTMENT ;
    PORT
      LAYER metal3 ;
      RECT 0.000 273.000 0.140 273.140 ;
    END
  END w_mask_in[10]
  PIN w_mask_in[11]
    DIRECTION INPUT ;
    USE SIGNAL ;
    SHAPE ABUTMENT ;
    PORT
      LAYER metal3 ;
      RECT 0.000 274.400 0.140 274.540 ;
    END
  END w_mask_in[11]
  PIN w_mask_in[12]
    DIRECTION INPUT ;
    USE SIGNAL ;
    SHAPE ABUTMENT ;
    PORT
      LAYER metal3 ;
      RECT 0.000 275.800 0.140 275.940 ;
    END
  END w_mask_in[12]
  PIN w_mask_in[13]
    DIRECTION INPUT ;
    USE SIGNAL ;
    SHAPE ABUTMENT ;
    PORT
      LAYER metal3 ;
      RECT 0.000 277.200 0.140 277.340 ;
    END
  END w_mask_in[13]
  PIN w_mask_in[14]
    DIRECTION INPUT ;
    USE SIGNAL ;
    SHAPE ABUTMENT ;
    PORT
      LAYER metal3 ;
      RECT 0.000 278.600 0.140 278.740 ;
    END
  END w_mask_in[14]
  PIN w_mask_in[15]
    DIRECTION INPUT ;
    USE SIGNAL ;
    SHAPE ABUTMENT ;
    PORT
      LAYER metal3 ;
      RECT 0.000 280.000 0.140 280.140 ;
    END
  END w_mask_in[15]
  PIN w_mask_in[16]
    DIRECTION INPUT ;
    USE SIGNAL ;
    SHAPE ABUTMENT ;
    PORT
      LAYER metal3 ;
      RECT 0.000 281.400 0.140 281.540 ;
    END
  END w_mask_in[16]
  PIN w_mask_in[17]
    DIRECTION INPUT ;
    USE SIGNAL ;
    SHAPE ABUTMENT ;
    PORT
      LAYER metal3 ;
      RECT 0.000 282.800 0.140 282.940 ;
    END
  END w_mask_in[17]
  PIN w_mask_in[18]
    DIRECTION INPUT ;
    USE SIGNAL ;
    SHAPE ABUTMENT ;
    PORT
      LAYER metal3 ;
      RECT 0.000 284.200 0.140 284.340 ;
    END
  END w_mask_in[18]
  PIN w_mask_in[19]
    DIRECTION INPUT ;
    USE SIGNAL ;
    SHAPE ABUTMENT ;
    PORT
      LAYER metal3 ;
      RECT 0.000 285.600 0.140 285.740 ;
    END
  END w_mask_in[19]
  PIN w_mask_in[20]
    DIRECTION INPUT ;
    USE SIGNAL ;
    SHAPE ABUTMENT ;
    PORT
      LAYER metal3 ;
      RECT 0.000 287.000 0.140 287.140 ;
    END
  END w_mask_in[20]
  PIN w_mask_in[21]
    DIRECTION INPUT ;
    USE SIGNAL ;
    SHAPE ABUTMENT ;
    PORT
      LAYER metal3 ;
      RECT 0.000 288.400 0.140 288.540 ;
    END
  END w_mask_in[21]
  PIN w_mask_in[22]
    DIRECTION INPUT ;
    USE SIGNAL ;
    SHAPE ABUTMENT ;
    PORT
      LAYER metal3 ;
      RECT 0.000 289.800 0.140 289.940 ;
    END
  END w_mask_in[22]
  PIN w_mask_in[23]
    DIRECTION INPUT ;
    USE SIGNAL ;
    SHAPE ABUTMENT ;
    PORT
      LAYER metal3 ;
      RECT 0.000 291.200 0.140 291.340 ;
    END
  END w_mask_in[23]
  PIN w_mask_in[24]
    DIRECTION INPUT ;
    USE SIGNAL ;
    SHAPE ABUTMENT ;
    PORT
      LAYER metal3 ;
      RECT 0.000 292.600 0.140 292.740 ;
    END
  END w_mask_in[24]
  PIN w_mask_in[25]
    DIRECTION INPUT ;
    USE SIGNAL ;
    SHAPE ABUTMENT ;
    PORT
      LAYER metal3 ;
      RECT 0.000 294.000 0.140 294.140 ;
    END
  END w_mask_in[25]
  PIN w_mask_in[26]
    DIRECTION INPUT ;
    USE SIGNAL ;
    SHAPE ABUTMENT ;
    PORT
      LAYER metal3 ;
      RECT 0.000 295.400 0.140 295.540 ;
    END
  END w_mask_in[26]
  PIN w_mask_in[27]
    DIRECTION INPUT ;
    USE SIGNAL ;
    SHAPE ABUTMENT ;
    PORT
      LAYER metal3 ;
      RECT 0.000 296.800 0.140 296.940 ;
    END
  END w_mask_in[27]
  PIN w_mask_in[28]
    DIRECTION INPUT ;
    USE SIGNAL ;
    SHAPE ABUTMENT ;
    PORT
      LAYER metal3 ;
      RECT 0.000 298.200 0.140 298.340 ;
    END
  END w_mask_in[28]
  PIN w_mask_in[29]
    DIRECTION INPUT ;
    USE SIGNAL ;
    SHAPE ABUTMENT ;
    PORT
      LAYER metal3 ;
      RECT 0.000 299.600 0.140 299.740 ;
    END
  END w_mask_in[29]
  PIN w_mask_in[30]
    DIRECTION INPUT ;
    USE SIGNAL ;
    SHAPE ABUTMENT ;
    PORT
      LAYER metal3 ;
      RECT 0.000 301.000 0.140 301.140 ;
    END
  END w_mask_in[30]
  PIN w_mask_in[31]
    DIRECTION INPUT ;
    USE SIGNAL ;
    SHAPE ABUTMENT ;
    PORT
      LAYER metal3 ;
      RECT 0.000 302.400 0.140 302.540 ;
    END
  END w_mask_in[31]
  PIN w_mask_in[32]
    DIRECTION INPUT ;
    USE SIGNAL ;
    SHAPE ABUTMENT ;
    PORT
      LAYER metal3 ;
      RECT 0.000 303.800 0.140 303.940 ;
    END
  END w_mask_in[32]
  PIN w_mask_in[33]
    DIRECTION INPUT ;
    USE SIGNAL ;
    SHAPE ABUTMENT ;
    PORT
      LAYER metal3 ;
      RECT 0.000 305.200 0.140 305.340 ;
    END
  END w_mask_in[33]
  PIN w_mask_in[34]
    DIRECTION INPUT ;
    USE SIGNAL ;
    SHAPE ABUTMENT ;
    PORT
      LAYER metal3 ;
      RECT 0.000 306.600 0.140 306.740 ;
    END
  END w_mask_in[34]
  PIN w_mask_in[35]
    DIRECTION INPUT ;
    USE SIGNAL ;
    SHAPE ABUTMENT ;
    PORT
      LAYER metal3 ;
      RECT 0.000 308.000 0.140 308.140 ;
    END
  END w_mask_in[35]
  PIN w_mask_in[36]
    DIRECTION INPUT ;
    USE SIGNAL ;
    SHAPE ABUTMENT ;
    PORT
      LAYER metal3 ;
      RECT 0.000 309.400 0.140 309.540 ;
    END
  END w_mask_in[36]
  PIN w_mask_in[37]
    DIRECTION INPUT ;
    USE SIGNAL ;
    SHAPE ABUTMENT ;
    PORT
      LAYER metal3 ;
      RECT 0.000 310.800 0.140 310.940 ;
    END
  END w_mask_in[37]
  PIN w_mask_in[38]
    DIRECTION INPUT ;
    USE SIGNAL ;
    SHAPE ABUTMENT ;
    PORT
      LAYER metal3 ;
      RECT 0.000 312.200 0.140 312.340 ;
    END
  END w_mask_in[38]
  PIN w_mask_in[39]
    DIRECTION INPUT ;
    USE SIGNAL ;
    SHAPE ABUTMENT ;
    PORT
      LAYER metal3 ;
      RECT 0.000 313.600 0.140 313.740 ;
    END
  END w_mask_in[39]
  PIN w_mask_in[40]
    DIRECTION INPUT ;
    USE SIGNAL ;
    SHAPE ABUTMENT ;
    PORT
      LAYER metal3 ;
      RECT 0.000 315.000 0.140 315.140 ;
    END
  END w_mask_in[40]
  PIN w_mask_in[41]
    DIRECTION INPUT ;
    USE SIGNAL ;
    SHAPE ABUTMENT ;
    PORT
      LAYER metal3 ;
      RECT 0.000 316.400 0.140 316.540 ;
    END
  END w_mask_in[41]
  PIN w_mask_in[42]
    DIRECTION INPUT ;
    USE SIGNAL ;
    SHAPE ABUTMENT ;
    PORT
      LAYER metal3 ;
      RECT 0.000 317.800 0.140 317.940 ;
    END
  END w_mask_in[42]
  PIN w_mask_in[43]
    DIRECTION INPUT ;
    USE SIGNAL ;
    SHAPE ABUTMENT ;
    PORT
      LAYER metal3 ;
      RECT 0.000 319.200 0.140 319.340 ;
    END
  END w_mask_in[43]
  PIN w_mask_in[44]
    DIRECTION INPUT ;
    USE SIGNAL ;
    SHAPE ABUTMENT ;
    PORT
      LAYER metal3 ;
      RECT 0.000 320.600 0.140 320.740 ;
    END
  END w_mask_in[44]
  PIN w_mask_in[45]
    DIRECTION INPUT ;
    USE SIGNAL ;
    SHAPE ABUTMENT ;
    PORT
      LAYER metal3 ;
      RECT 0.000 322.000 0.140 322.140 ;
    END
  END w_mask_in[45]
  PIN w_mask_in[46]
    DIRECTION INPUT ;
    USE SIGNAL ;
    SHAPE ABUTMENT ;
    PORT
      LAYER metal3 ;
      RECT 0.000 323.400 0.140 323.540 ;
    END
  END w_mask_in[46]
  PIN w_mask_in[47]
    DIRECTION INPUT ;
    USE SIGNAL ;
    SHAPE ABUTMENT ;
    PORT
      LAYER metal3 ;
      RECT 0.000 324.800 0.140 324.940 ;
    END
  END w_mask_in[47]
  PIN w_mask_in[48]
    DIRECTION INPUT ;
    USE SIGNAL ;
    SHAPE ABUTMENT ;
    PORT
      LAYER metal3 ;
      RECT 0.000 326.200 0.140 326.340 ;
    END
  END w_mask_in[48]
  PIN w_mask_in[49]
    DIRECTION INPUT ;
    USE SIGNAL ;
    SHAPE ABUTMENT ;
    PORT
      LAYER metal3 ;
      RECT 0.000 327.600 0.140 327.740 ;
    END
  END w_mask_in[49]
  PIN w_mask_in[50]
    DIRECTION INPUT ;
    USE SIGNAL ;
    SHAPE ABUTMENT ;
    PORT
      LAYER metal3 ;
      RECT 0.000 329.000 0.140 329.140 ;
    END
  END w_mask_in[50]
  PIN w_mask_in[51]
    DIRECTION INPUT ;
    USE SIGNAL ;
    SHAPE ABUTMENT ;
    PORT
      LAYER metal3 ;
      RECT 0.000 330.400 0.140 330.540 ;
    END
  END w_mask_in[51]
  PIN w_mask_in[52]
    DIRECTION INPUT ;
    USE SIGNAL ;
    SHAPE ABUTMENT ;
    PORT
      LAYER metal3 ;
      RECT 0.000 331.800 0.140 331.940 ;
    END
  END w_mask_in[52]
  PIN w_mask_in[53]
    DIRECTION INPUT ;
    USE SIGNAL ;
    SHAPE ABUTMENT ;
    PORT
      LAYER metal3 ;
      RECT 0.000 333.200 0.140 333.340 ;
    END
  END w_mask_in[53]
  PIN w_mask_in[54]
    DIRECTION INPUT ;
    USE SIGNAL ;
    SHAPE ABUTMENT ;
    PORT
      LAYER metal3 ;
      RECT 0.000 334.600 0.140 334.740 ;
    END
  END w_mask_in[54]
  PIN w_mask_in[55]
    DIRECTION INPUT ;
    USE SIGNAL ;
    SHAPE ABUTMENT ;
    PORT
      LAYER metal3 ;
      RECT 0.000 336.000 0.140 336.140 ;
    END
  END w_mask_in[55]
  PIN w_mask_in[56]
    DIRECTION INPUT ;
    USE SIGNAL ;
    SHAPE ABUTMENT ;
    PORT
      LAYER metal3 ;
      RECT 0.000 337.400 0.140 337.540 ;
    END
  END w_mask_in[56]
  PIN w_mask_in[57]
    DIRECTION INPUT ;
    USE SIGNAL ;
    SHAPE ABUTMENT ;
    PORT
      LAYER metal3 ;
      RECT 0.000 338.800 0.140 338.940 ;
    END
  END w_mask_in[57]
  PIN w_mask_in[58]
    DIRECTION INPUT ;
    USE SIGNAL ;
    SHAPE ABUTMENT ;
    PORT
      LAYER metal3 ;
      RECT 0.000 340.200 0.140 340.340 ;
    END
  END w_mask_in[58]
  PIN w_mask_in[59]
    DIRECTION INPUT ;
    USE SIGNAL ;
    SHAPE ABUTMENT ;
    PORT
      LAYER metal3 ;
      RECT 0.000 341.600 0.140 341.740 ;
    END
  END w_mask_in[59]
  PIN w_mask_in[60]
    DIRECTION INPUT ;
    USE SIGNAL ;
    SHAPE ABUTMENT ;
    PORT
      LAYER metal3 ;
      RECT 0.000 343.000 0.140 343.140 ;
    END
  END w_mask_in[60]
  PIN w_mask_in[61]
    DIRECTION INPUT ;
    USE SIGNAL ;
    SHAPE ABUTMENT ;
    PORT
      LAYER metal3 ;
      RECT 0.000 344.400 0.140 344.540 ;
    END
  END w_mask_in[61]
  PIN w_mask_in[62]
    DIRECTION INPUT ;
    USE SIGNAL ;
    SHAPE ABUTMENT ;
    PORT
      LAYER metal3 ;
      RECT 0.000 345.800 0.140 345.940 ;
    END
  END w_mask_in[62]
  PIN w_mask_in[63]
    DIRECTION INPUT ;
    USE SIGNAL ;
    SHAPE ABUTMENT ;
    PORT
      LAYER metal3 ;
      RECT 0.000 347.200 0.140 347.340 ;
    END
  END w_mask_in[63]
  PIN w_mask_in[64]
    DIRECTION INPUT ;
    USE SIGNAL ;
    SHAPE ABUTMENT ;
    PORT
      LAYER metal3 ;
      RECT 0.000 348.600 0.140 348.740 ;
    END
  END w_mask_in[64]
  PIN w_mask_in[65]
    DIRECTION INPUT ;
    USE SIGNAL ;
    SHAPE ABUTMENT ;
    PORT
      LAYER metal3 ;
      RECT 0.000 350.000 0.140 350.140 ;
    END
  END w_mask_in[65]
  PIN w_mask_in[66]
    DIRECTION INPUT ;
    USE SIGNAL ;
    SHAPE ABUTMENT ;
    PORT
      LAYER metal3 ;
      RECT 0.000 351.400 0.140 351.540 ;
    END
  END w_mask_in[66]
  PIN w_mask_in[67]
    DIRECTION INPUT ;
    USE SIGNAL ;
    SHAPE ABUTMENT ;
    PORT
      LAYER metal3 ;
      RECT 0.000 352.800 0.140 352.940 ;
    END
  END w_mask_in[67]
  PIN w_mask_in[68]
    DIRECTION INPUT ;
    USE SIGNAL ;
    SHAPE ABUTMENT ;
    PORT
      LAYER metal3 ;
      RECT 0.000 354.200 0.140 354.340 ;
    END
  END w_mask_in[68]
  PIN w_mask_in[69]
    DIRECTION INPUT ;
    USE SIGNAL ;
    SHAPE ABUTMENT ;
    PORT
      LAYER metal3 ;
      RECT 0.000 355.600 0.140 355.740 ;
    END
  END w_mask_in[69]
  PIN w_mask_in[70]
    DIRECTION INPUT ;
    USE SIGNAL ;
    SHAPE ABUTMENT ;
    PORT
      LAYER metal3 ;
      RECT 0.000 357.000 0.140 357.140 ;
    END
  END w_mask_in[70]
  PIN w_mask_in[71]
    DIRECTION INPUT ;
    USE SIGNAL ;
    SHAPE ABUTMENT ;
    PORT
      LAYER metal3 ;
      RECT 0.000 358.400 0.140 358.540 ;
    END
  END w_mask_in[71]
  PIN w_mask_in[72]
    DIRECTION INPUT ;
    USE SIGNAL ;
    SHAPE ABUTMENT ;
    PORT
      LAYER metal3 ;
      RECT 0.000 359.800 0.140 359.940 ;
    END
  END w_mask_in[72]
  PIN w_mask_in[73]
    DIRECTION INPUT ;
    USE SIGNAL ;
    SHAPE ABUTMENT ;
    PORT
      LAYER metal3 ;
      RECT 0.000 361.200 0.140 361.340 ;
    END
  END w_mask_in[73]
  PIN w_mask_in[74]
    DIRECTION INPUT ;
    USE SIGNAL ;
    SHAPE ABUTMENT ;
    PORT
      LAYER metal3 ;
      RECT 0.000 362.600 0.140 362.740 ;
    END
  END w_mask_in[74]
  PIN w_mask_in[75]
    DIRECTION INPUT ;
    USE SIGNAL ;
    SHAPE ABUTMENT ;
    PORT
      LAYER metal3 ;
      RECT 0.000 364.000 0.140 364.140 ;
    END
  END w_mask_in[75]
  PIN w_mask_in[76]
    DIRECTION INPUT ;
    USE SIGNAL ;
    SHAPE ABUTMENT ;
    PORT
      LAYER metal3 ;
      RECT 0.000 365.400 0.140 365.540 ;
    END
  END w_mask_in[76]
  PIN w_mask_in[77]
    DIRECTION INPUT ;
    USE SIGNAL ;
    SHAPE ABUTMENT ;
    PORT
      LAYER metal3 ;
      RECT 0.000 366.800 0.140 366.940 ;
    END
  END w_mask_in[77]
  PIN w_mask_in[78]
    DIRECTION INPUT ;
    USE SIGNAL ;
    SHAPE ABUTMENT ;
    PORT
      LAYER metal3 ;
      RECT 0.000 368.200 0.140 368.340 ;
    END
  END w_mask_in[78]
  PIN w_mask_in[79]
    DIRECTION INPUT ;
    USE SIGNAL ;
    SHAPE ABUTMENT ;
    PORT
      LAYER metal3 ;
      RECT 0.000 369.600 0.140 369.740 ;
    END
  END w_mask_in[79]
  PIN w_mask_in[80]
    DIRECTION INPUT ;
    USE SIGNAL ;
    SHAPE ABUTMENT ;
    PORT
      LAYER metal3 ;
      RECT 0.000 371.000 0.140 371.140 ;
    END
  END w_mask_in[80]
  PIN w_mask_in[81]
    DIRECTION INPUT ;
    USE SIGNAL ;
    SHAPE ABUTMENT ;
    PORT
      LAYER metal3 ;
      RECT 0.000 372.400 0.140 372.540 ;
    END
  END w_mask_in[81]
  PIN w_mask_in[82]
    DIRECTION INPUT ;
    USE SIGNAL ;
    SHAPE ABUTMENT ;
    PORT
      LAYER metal3 ;
      RECT 0.000 373.800 0.140 373.940 ;
    END
  END w_mask_in[82]
  PIN w_mask_in[83]
    DIRECTION INPUT ;
    USE SIGNAL ;
    SHAPE ABUTMENT ;
    PORT
      LAYER metal3 ;
      RECT 0.000 375.200 0.140 375.340 ;
    END
  END w_mask_in[83]
  PIN w_mask_in[84]
    DIRECTION INPUT ;
    USE SIGNAL ;
    SHAPE ABUTMENT ;
    PORT
      LAYER metal3 ;
      RECT 0.000 376.600 0.140 376.740 ;
    END
  END w_mask_in[84]
  PIN w_mask_in[85]
    DIRECTION INPUT ;
    USE SIGNAL ;
    SHAPE ABUTMENT ;
    PORT
      LAYER metal3 ;
      RECT 0.000 378.000 0.140 378.140 ;
    END
  END w_mask_in[85]
  PIN w_mask_in[86]
    DIRECTION INPUT ;
    USE SIGNAL ;
    SHAPE ABUTMENT ;
    PORT
      LAYER metal3 ;
      RECT 0.000 379.400 0.140 379.540 ;
    END
  END w_mask_in[86]
  PIN w_mask_in[87]
    DIRECTION INPUT ;
    USE SIGNAL ;
    SHAPE ABUTMENT ;
    PORT
      LAYER metal3 ;
      RECT 0.000 380.800 0.140 380.940 ;
    END
  END w_mask_in[87]
  PIN w_mask_in[88]
    DIRECTION INPUT ;
    USE SIGNAL ;
    SHAPE ABUTMENT ;
    PORT
      LAYER metal3 ;
      RECT 0.000 382.200 0.140 382.340 ;
    END
  END w_mask_in[88]
  PIN w_mask_in[89]
    DIRECTION INPUT ;
    USE SIGNAL ;
    SHAPE ABUTMENT ;
    PORT
      LAYER metal3 ;
      RECT 0.000 383.600 0.140 383.740 ;
    END
  END w_mask_in[89]
  PIN w_mask_in[90]
    DIRECTION INPUT ;
    USE SIGNAL ;
    SHAPE ABUTMENT ;
    PORT
      LAYER metal3 ;
      RECT 0.000 385.000 0.140 385.140 ;
    END
  END w_mask_in[90]
  PIN w_mask_in[91]
    DIRECTION INPUT ;
    USE SIGNAL ;
    SHAPE ABUTMENT ;
    PORT
      LAYER metal3 ;
      RECT 0.000 386.400 0.140 386.540 ;
    END
  END w_mask_in[91]
  PIN w_mask_in[92]
    DIRECTION INPUT ;
    USE SIGNAL ;
    SHAPE ABUTMENT ;
    PORT
      LAYER metal3 ;
      RECT 0.000 387.800 0.140 387.940 ;
    END
  END w_mask_in[92]
  PIN w_mask_in[93]
    DIRECTION INPUT ;
    USE SIGNAL ;
    SHAPE ABUTMENT ;
    PORT
      LAYER metal3 ;
      RECT 0.000 389.200 0.140 389.340 ;
    END
  END w_mask_in[93]
  PIN w_mask_in[94]
    DIRECTION INPUT ;
    USE SIGNAL ;
    SHAPE ABUTMENT ;
    PORT
      LAYER metal3 ;
      RECT 0.000 390.600 0.140 390.740 ;
    END
  END w_mask_in[94]
  PIN w_mask_in[95]
    DIRECTION INPUT ;
    USE SIGNAL ;
    SHAPE ABUTMENT ;
    PORT
      LAYER metal3 ;
      RECT 0.000 392.000 0.140 392.140 ;
    END
  END w_mask_in[95]
  PIN w_mask_in[96]
    DIRECTION INPUT ;
    USE SIGNAL ;
    SHAPE ABUTMENT ;
    PORT
      LAYER metal3 ;
      RECT 0.000 393.400 0.140 393.540 ;
    END
  END w_mask_in[96]
  PIN w_mask_in[97]
    DIRECTION INPUT ;
    USE SIGNAL ;
    SHAPE ABUTMENT ;
    PORT
      LAYER metal3 ;
      RECT 0.000 394.800 0.140 394.940 ;
    END
  END w_mask_in[97]
  PIN w_mask_in[98]
    DIRECTION INPUT ;
    USE SIGNAL ;
    SHAPE ABUTMENT ;
    PORT
      LAYER metal3 ;
      RECT 0.000 396.200 0.140 396.340 ;
    END
  END w_mask_in[98]
  PIN w_mask_in[99]
    DIRECTION INPUT ;
    USE SIGNAL ;
    SHAPE ABUTMENT ;
    PORT
      LAYER metal3 ;
      RECT 0.000 397.600 0.140 397.740 ;
    END
  END w_mask_in[99]
  PIN w_mask_in[100]
    DIRECTION INPUT ;
    USE SIGNAL ;
    SHAPE ABUTMENT ;
    PORT
      LAYER metal3 ;
      RECT 0.000 399.000 0.140 399.140 ;
    END
  END w_mask_in[100]
  PIN w_mask_in[101]
    DIRECTION INPUT ;
    USE SIGNAL ;
    SHAPE ABUTMENT ;
    PORT
      LAYER metal3 ;
      RECT 0.000 400.400 0.140 400.540 ;
    END
  END w_mask_in[101]
  PIN w_mask_in[102]
    DIRECTION INPUT ;
    USE SIGNAL ;
    SHAPE ABUTMENT ;
    PORT
      LAYER metal3 ;
      RECT 0.000 401.800 0.140 401.940 ;
    END
  END w_mask_in[102]
  PIN w_mask_in[103]
    DIRECTION INPUT ;
    USE SIGNAL ;
    SHAPE ABUTMENT ;
    PORT
      LAYER metal3 ;
      RECT 0.000 403.200 0.140 403.340 ;
    END
  END w_mask_in[103]
  PIN w_mask_in[104]
    DIRECTION INPUT ;
    USE SIGNAL ;
    SHAPE ABUTMENT ;
    PORT
      LAYER metal3 ;
      RECT 0.000 404.600 0.140 404.740 ;
    END
  END w_mask_in[104]
  PIN w_mask_in[105]
    DIRECTION INPUT ;
    USE SIGNAL ;
    SHAPE ABUTMENT ;
    PORT
      LAYER metal3 ;
      RECT 0.000 406.000 0.140 406.140 ;
    END
  END w_mask_in[105]
  PIN w_mask_in[106]
    DIRECTION INPUT ;
    USE SIGNAL ;
    SHAPE ABUTMENT ;
    PORT
      LAYER metal3 ;
      RECT 0.000 407.400 0.140 407.540 ;
    END
  END w_mask_in[106]
  PIN w_mask_in[107]
    DIRECTION INPUT ;
    USE SIGNAL ;
    SHAPE ABUTMENT ;
    PORT
      LAYER metal3 ;
      RECT 0.000 408.800 0.140 408.940 ;
    END
  END w_mask_in[107]
  PIN w_mask_in[108]
    DIRECTION INPUT ;
    USE SIGNAL ;
    SHAPE ABUTMENT ;
    PORT
      LAYER metal3 ;
      RECT 0.000 410.200 0.140 410.340 ;
    END
  END w_mask_in[108]
  PIN w_mask_in[109]
    DIRECTION INPUT ;
    USE SIGNAL ;
    SHAPE ABUTMENT ;
    PORT
      LAYER metal3 ;
      RECT 0.000 411.600 0.140 411.740 ;
    END
  END w_mask_in[109]
  PIN w_mask_in[110]
    DIRECTION INPUT ;
    USE SIGNAL ;
    SHAPE ABUTMENT ;
    PORT
      LAYER metal3 ;
      RECT 0.000 413.000 0.140 413.140 ;
    END
  END w_mask_in[110]
  PIN w_mask_in[111]
    DIRECTION INPUT ;
    USE SIGNAL ;
    SHAPE ABUTMENT ;
    PORT
      LAYER metal3 ;
      RECT 0.000 414.400 0.140 414.540 ;
    END
  END w_mask_in[111]
  PIN w_mask_in[112]
    DIRECTION INPUT ;
    USE SIGNAL ;
    SHAPE ABUTMENT ;
    PORT
      LAYER metal3 ;
      RECT 0.000 415.800 0.140 415.940 ;
    END
  END w_mask_in[112]
  PIN w_mask_in[113]
    DIRECTION INPUT ;
    USE SIGNAL ;
    SHAPE ABUTMENT ;
    PORT
      LAYER metal3 ;
      RECT 0.000 417.200 0.140 417.340 ;
    END
  END w_mask_in[113]
  PIN w_mask_in[114]
    DIRECTION INPUT ;
    USE SIGNAL ;
    SHAPE ABUTMENT ;
    PORT
      LAYER metal3 ;
      RECT 0.000 418.600 0.140 418.740 ;
    END
  END w_mask_in[114]
  PIN w_mask_in[115]
    DIRECTION INPUT ;
    USE SIGNAL ;
    SHAPE ABUTMENT ;
    PORT
      LAYER metal3 ;
      RECT 0.000 420.000 0.140 420.140 ;
    END
  END w_mask_in[115]
  PIN w_mask_in[116]
    DIRECTION INPUT ;
    USE SIGNAL ;
    SHAPE ABUTMENT ;
    PORT
      LAYER metal3 ;
      RECT 0.000 421.400 0.140 421.540 ;
    END
  END w_mask_in[116]
  PIN w_mask_in[117]
    DIRECTION INPUT ;
    USE SIGNAL ;
    SHAPE ABUTMENT ;
    PORT
      LAYER metal3 ;
      RECT 0.000 422.800 0.140 422.940 ;
    END
  END w_mask_in[117]
  PIN w_mask_in[118]
    DIRECTION INPUT ;
    USE SIGNAL ;
    SHAPE ABUTMENT ;
    PORT
      LAYER metal3 ;
      RECT 0.000 424.200 0.140 424.340 ;
    END
  END w_mask_in[118]
  PIN w_mask_in[119]
    DIRECTION INPUT ;
    USE SIGNAL ;
    SHAPE ABUTMENT ;
    PORT
      LAYER metal3 ;
      RECT 0.000 425.600 0.140 425.740 ;
    END
  END w_mask_in[119]
  PIN w_mask_in[120]
    DIRECTION INPUT ;
    USE SIGNAL ;
    SHAPE ABUTMENT ;
    PORT
      LAYER metal3 ;
      RECT 0.000 427.000 0.140 427.140 ;
    END
  END w_mask_in[120]
  PIN w_mask_in[121]
    DIRECTION INPUT ;
    USE SIGNAL ;
    SHAPE ABUTMENT ;
    PORT
      LAYER metal3 ;
      RECT 0.000 428.400 0.140 428.540 ;
    END
  END w_mask_in[121]
  PIN w_mask_in[122]
    DIRECTION INPUT ;
    USE SIGNAL ;
    SHAPE ABUTMENT ;
    PORT
      LAYER metal3 ;
      RECT 0.000 429.800 0.140 429.940 ;
    END
  END w_mask_in[122]
  PIN w_mask_in[123]
    DIRECTION INPUT ;
    USE SIGNAL ;
    SHAPE ABUTMENT ;
    PORT
      LAYER metal3 ;
      RECT 0.000 431.200 0.140 431.340 ;
    END
  END w_mask_in[123]
  PIN w_mask_in[124]
    DIRECTION INPUT ;
    USE SIGNAL ;
    SHAPE ABUTMENT ;
    PORT
      LAYER metal3 ;
      RECT 0.000 432.600 0.140 432.740 ;
    END
  END w_mask_in[124]
  PIN w_mask_in[125]
    DIRECTION INPUT ;
    USE SIGNAL ;
    SHAPE ABUTMENT ;
    PORT
      LAYER metal3 ;
      RECT 0.000 434.000 0.140 434.140 ;
    END
  END w_mask_in[125]
  PIN w_mask_in[126]
    DIRECTION INPUT ;
    USE SIGNAL ;
    SHAPE ABUTMENT ;
    PORT
      LAYER metal3 ;
      RECT 0.000 435.400 0.140 435.540 ;
    END
  END w_mask_in[126]
  PIN w_mask_in[127]
    DIRECTION INPUT ;
    USE SIGNAL ;
    SHAPE ABUTMENT ;
    PORT
      LAYER metal3 ;
      RECT 0.000 436.800 0.140 436.940 ;
    END
  END w_mask_in[127]
  PIN w_mask_in[128]
    DIRECTION INPUT ;
    USE SIGNAL ;
    SHAPE ABUTMENT ;
    PORT
      LAYER metal3 ;
      RECT 0.000 438.200 0.140 438.340 ;
    END
  END w_mask_in[128]
  PIN w_mask_in[129]
    DIRECTION INPUT ;
    USE SIGNAL ;
    SHAPE ABUTMENT ;
    PORT
      LAYER metal3 ;
      RECT 0.000 439.600 0.140 439.740 ;
    END
  END w_mask_in[129]
  PIN w_mask_in[130]
    DIRECTION INPUT ;
    USE SIGNAL ;
    SHAPE ABUTMENT ;
    PORT
      LAYER metal3 ;
      RECT 0.000 441.000 0.140 441.140 ;
    END
  END w_mask_in[130]
  PIN w_mask_in[131]
    DIRECTION INPUT ;
    USE SIGNAL ;
    SHAPE ABUTMENT ;
    PORT
      LAYER metal3 ;
      RECT 0.000 442.400 0.140 442.540 ;
    END
  END w_mask_in[131]
  PIN w_mask_in[132]
    DIRECTION INPUT ;
    USE SIGNAL ;
    SHAPE ABUTMENT ;
    PORT
      LAYER metal3 ;
      RECT 0.000 443.800 0.140 443.940 ;
    END
  END w_mask_in[132]
  PIN w_mask_in[133]
    DIRECTION INPUT ;
    USE SIGNAL ;
    SHAPE ABUTMENT ;
    PORT
      LAYER metal3 ;
      RECT 0.000 445.200 0.140 445.340 ;
    END
  END w_mask_in[133]
  PIN w_mask_in[134]
    DIRECTION INPUT ;
    USE SIGNAL ;
    SHAPE ABUTMENT ;
    PORT
      LAYER metal3 ;
      RECT 0.000 446.600 0.140 446.740 ;
    END
  END w_mask_in[134]
  PIN w_mask_in[135]
    DIRECTION INPUT ;
    USE SIGNAL ;
    SHAPE ABUTMENT ;
    PORT
      LAYER metal3 ;
      RECT 0.000 448.000 0.140 448.140 ;
    END
  END w_mask_in[135]
  PIN w_mask_in[136]
    DIRECTION INPUT ;
    USE SIGNAL ;
    SHAPE ABUTMENT ;
    PORT
      LAYER metal3 ;
      RECT 0.000 449.400 0.140 449.540 ;
    END
  END w_mask_in[136]
  PIN w_mask_in[137]
    DIRECTION INPUT ;
    USE SIGNAL ;
    SHAPE ABUTMENT ;
    PORT
      LAYER metal3 ;
      RECT 0.000 450.800 0.140 450.940 ;
    END
  END w_mask_in[137]
  PIN w_mask_in[138]
    DIRECTION INPUT ;
    USE SIGNAL ;
    SHAPE ABUTMENT ;
    PORT
      LAYER metal3 ;
      RECT 0.000 452.200 0.140 452.340 ;
    END
  END w_mask_in[138]
  PIN w_mask_in[139]
    DIRECTION INPUT ;
    USE SIGNAL ;
    SHAPE ABUTMENT ;
    PORT
      LAYER metal3 ;
      RECT 0.000 453.600 0.140 453.740 ;
    END
  END w_mask_in[139]
  PIN w_mask_in[140]
    DIRECTION INPUT ;
    USE SIGNAL ;
    SHAPE ABUTMENT ;
    PORT
      LAYER metal3 ;
      RECT 0.000 455.000 0.140 455.140 ;
    END
  END w_mask_in[140]
  PIN w_mask_in[141]
    DIRECTION INPUT ;
    USE SIGNAL ;
    SHAPE ABUTMENT ;
    PORT
      LAYER metal3 ;
      RECT 0.000 456.400 0.140 456.540 ;
    END
  END w_mask_in[141]
  PIN w_mask_in[142]
    DIRECTION INPUT ;
    USE SIGNAL ;
    SHAPE ABUTMENT ;
    PORT
      LAYER metal3 ;
      RECT 0.000 457.800 0.140 457.940 ;
    END
  END w_mask_in[142]
  PIN w_mask_in[143]
    DIRECTION INPUT ;
    USE SIGNAL ;
    SHAPE ABUTMENT ;
    PORT
      LAYER metal3 ;
      RECT 0.000 459.200 0.140 459.340 ;
    END
  END w_mask_in[143]
  PIN w_mask_in[144]
    DIRECTION INPUT ;
    USE SIGNAL ;
    SHAPE ABUTMENT ;
    PORT
      LAYER metal3 ;
      RECT 0.000 460.600 0.140 460.740 ;
    END
  END w_mask_in[144]
  PIN w_mask_in[145]
    DIRECTION INPUT ;
    USE SIGNAL ;
    SHAPE ABUTMENT ;
    PORT
      LAYER metal3 ;
      RECT 0.000 462.000 0.140 462.140 ;
    END
  END w_mask_in[145]
  PIN w_mask_in[146]
    DIRECTION INPUT ;
    USE SIGNAL ;
    SHAPE ABUTMENT ;
    PORT
      LAYER metal3 ;
      RECT 0.000 463.400 0.140 463.540 ;
    END
  END w_mask_in[146]
  PIN w_mask_in[147]
    DIRECTION INPUT ;
    USE SIGNAL ;
    SHAPE ABUTMENT ;
    PORT
      LAYER metal3 ;
      RECT 0.000 464.800 0.140 464.940 ;
    END
  END w_mask_in[147]
  PIN w_mask_in[148]
    DIRECTION INPUT ;
    USE SIGNAL ;
    SHAPE ABUTMENT ;
    PORT
      LAYER metal3 ;
      RECT 0.000 466.200 0.140 466.340 ;
    END
  END w_mask_in[148]
  PIN w_mask_in[149]
    DIRECTION INPUT ;
    USE SIGNAL ;
    SHAPE ABUTMENT ;
    PORT
      LAYER metal3 ;
      RECT 0.000 467.600 0.140 467.740 ;
    END
  END w_mask_in[149]
  PIN w_mask_in[150]
    DIRECTION INPUT ;
    USE SIGNAL ;
    SHAPE ABUTMENT ;
    PORT
      LAYER metal3 ;
      RECT 0.000 469.000 0.140 469.140 ;
    END
  END w_mask_in[150]
  PIN w_mask_in[151]
    DIRECTION INPUT ;
    USE SIGNAL ;
    SHAPE ABUTMENT ;
    PORT
      LAYER metal3 ;
      RECT 0.000 470.400 0.140 470.540 ;
    END
  END w_mask_in[151]
  PIN w_mask_in[152]
    DIRECTION INPUT ;
    USE SIGNAL ;
    SHAPE ABUTMENT ;
    PORT
      LAYER metal3 ;
      RECT 0.000 471.800 0.140 471.940 ;
    END
  END w_mask_in[152]
  PIN w_mask_in[153]
    DIRECTION INPUT ;
    USE SIGNAL ;
    SHAPE ABUTMENT ;
    PORT
      LAYER metal3 ;
      RECT 0.000 473.200 0.140 473.340 ;
    END
  END w_mask_in[153]
  PIN w_mask_in[154]
    DIRECTION INPUT ;
    USE SIGNAL ;
    SHAPE ABUTMENT ;
    PORT
      LAYER metal3 ;
      RECT 0.000 474.600 0.140 474.740 ;
    END
  END w_mask_in[154]
  PIN w_mask_in[155]
    DIRECTION INPUT ;
    USE SIGNAL ;
    SHAPE ABUTMENT ;
    PORT
      LAYER metal3 ;
      RECT 0.000 476.000 0.140 476.140 ;
    END
  END w_mask_in[155]
  PIN w_mask_in[156]
    DIRECTION INPUT ;
    USE SIGNAL ;
    SHAPE ABUTMENT ;
    PORT
      LAYER metal3 ;
      RECT 0.000 477.400 0.140 477.540 ;
    END
  END w_mask_in[156]
  PIN w_mask_in[157]
    DIRECTION INPUT ;
    USE SIGNAL ;
    SHAPE ABUTMENT ;
    PORT
      LAYER metal3 ;
      RECT 0.000 478.800 0.140 478.940 ;
    END
  END w_mask_in[157]
  PIN w_mask_in[158]
    DIRECTION INPUT ;
    USE SIGNAL ;
    SHAPE ABUTMENT ;
    PORT
      LAYER metal3 ;
      RECT 0.000 480.200 0.140 480.340 ;
    END
  END w_mask_in[158]
  PIN w_mask_in[159]
    DIRECTION INPUT ;
    USE SIGNAL ;
    SHAPE ABUTMENT ;
    PORT
      LAYER metal3 ;
      RECT 0.000 481.600 0.140 481.740 ;
    END
  END w_mask_in[159]
  PIN w_mask_in[160]
    DIRECTION INPUT ;
    USE SIGNAL ;
    SHAPE ABUTMENT ;
    PORT
      LAYER metal3 ;
      RECT 0.000 483.000 0.140 483.140 ;
    END
  END w_mask_in[160]
  PIN w_mask_in[161]
    DIRECTION INPUT ;
    USE SIGNAL ;
    SHAPE ABUTMENT ;
    PORT
      LAYER metal3 ;
      RECT 0.000 484.400 0.140 484.540 ;
    END
  END w_mask_in[161]
  PIN w_mask_in[162]
    DIRECTION INPUT ;
    USE SIGNAL ;
    SHAPE ABUTMENT ;
    PORT
      LAYER metal3 ;
      RECT 0.000 485.800 0.140 485.940 ;
    END
  END w_mask_in[162]
  PIN w_mask_in[163]
    DIRECTION INPUT ;
    USE SIGNAL ;
    SHAPE ABUTMENT ;
    PORT
      LAYER metal3 ;
      RECT 0.000 487.200 0.140 487.340 ;
    END
  END w_mask_in[163]
  PIN w_mask_in[164]
    DIRECTION INPUT ;
    USE SIGNAL ;
    SHAPE ABUTMENT ;
    PORT
      LAYER metal3 ;
      RECT 0.000 488.600 0.140 488.740 ;
    END
  END w_mask_in[164]
  PIN w_mask_in[165]
    DIRECTION INPUT ;
    USE SIGNAL ;
    SHAPE ABUTMENT ;
    PORT
      LAYER metal3 ;
      RECT 0.000 490.000 0.140 490.140 ;
    END
  END w_mask_in[165]
  PIN w_mask_in[166]
    DIRECTION INPUT ;
    USE SIGNAL ;
    SHAPE ABUTMENT ;
    PORT
      LAYER metal3 ;
      RECT 0.000 491.400 0.140 491.540 ;
    END
  END w_mask_in[166]
  PIN w_mask_in[167]
    DIRECTION INPUT ;
    USE SIGNAL ;
    SHAPE ABUTMENT ;
    PORT
      LAYER metal3 ;
      RECT 0.000 492.800 0.140 492.940 ;
    END
  END w_mask_in[167]
  PIN w_mask_in[168]
    DIRECTION INPUT ;
    USE SIGNAL ;
    SHAPE ABUTMENT ;
    PORT
      LAYER metal3 ;
      RECT 0.000 494.200 0.140 494.340 ;
    END
  END w_mask_in[168]
  PIN w_mask_in[169]
    DIRECTION INPUT ;
    USE SIGNAL ;
    SHAPE ABUTMENT ;
    PORT
      LAYER metal3 ;
      RECT 0.000 495.600 0.140 495.740 ;
    END
  END w_mask_in[169]
  PIN w_mask_in[170]
    DIRECTION INPUT ;
    USE SIGNAL ;
    SHAPE ABUTMENT ;
    PORT
      LAYER metal3 ;
      RECT 0.000 497.000 0.140 497.140 ;
    END
  END w_mask_in[170]
  PIN w_mask_in[171]
    DIRECTION INPUT ;
    USE SIGNAL ;
    SHAPE ABUTMENT ;
    PORT
      LAYER metal3 ;
      RECT 0.000 498.400 0.140 498.540 ;
    END
  END w_mask_in[171]
  PIN w_mask_in[172]
    DIRECTION INPUT ;
    USE SIGNAL ;
    SHAPE ABUTMENT ;
    PORT
      LAYER metal3 ;
      RECT 0.000 499.800 0.140 499.940 ;
    END
  END w_mask_in[172]
  PIN w_mask_in[173]
    DIRECTION INPUT ;
    USE SIGNAL ;
    SHAPE ABUTMENT ;
    PORT
      LAYER metal3 ;
      RECT 0.000 501.200 0.140 501.340 ;
    END
  END w_mask_in[173]
  PIN w_mask_in[174]
    DIRECTION INPUT ;
    USE SIGNAL ;
    SHAPE ABUTMENT ;
    PORT
      LAYER metal3 ;
      RECT 0.000 502.600 0.140 502.740 ;
    END
  END w_mask_in[174]
  PIN w_mask_in[175]
    DIRECTION INPUT ;
    USE SIGNAL ;
    SHAPE ABUTMENT ;
    PORT
      LAYER metal3 ;
      RECT 0.000 504.000 0.140 504.140 ;
    END
  END w_mask_in[175]
  PIN w_mask_in[176]
    DIRECTION INPUT ;
    USE SIGNAL ;
    SHAPE ABUTMENT ;
    PORT
      LAYER metal3 ;
      RECT 0.000 505.400 0.140 505.540 ;
    END
  END w_mask_in[176]
  PIN w_mask_in[177]
    DIRECTION INPUT ;
    USE SIGNAL ;
    SHAPE ABUTMENT ;
    PORT
      LAYER metal3 ;
      RECT 0.000 506.800 0.140 506.940 ;
    END
  END w_mask_in[177]
  PIN w_mask_in[178]
    DIRECTION INPUT ;
    USE SIGNAL ;
    SHAPE ABUTMENT ;
    PORT
      LAYER metal3 ;
      RECT 0.000 508.200 0.140 508.340 ;
    END
  END w_mask_in[178]
  PIN w_mask_in[179]
    DIRECTION INPUT ;
    USE SIGNAL ;
    SHAPE ABUTMENT ;
    PORT
      LAYER metal3 ;
      RECT 0.000 509.600 0.140 509.740 ;
    END
  END w_mask_in[179]
  PIN w_mask_in[180]
    DIRECTION INPUT ;
    USE SIGNAL ;
    SHAPE ABUTMENT ;
    PORT
      LAYER metal3 ;
      RECT 0.000 511.000 0.140 511.140 ;
    END
  END w_mask_in[180]
  PIN w_mask_in[181]
    DIRECTION INPUT ;
    USE SIGNAL ;
    SHAPE ABUTMENT ;
    PORT
      LAYER metal3 ;
      RECT 0.000 512.400 0.140 512.540 ;
    END
  END w_mask_in[181]
  PIN w_mask_in[182]
    DIRECTION INPUT ;
    USE SIGNAL ;
    SHAPE ABUTMENT ;
    PORT
      LAYER metal3 ;
      RECT 0.000 513.800 0.140 513.940 ;
    END
  END w_mask_in[182]
  PIN w_mask_in[183]
    DIRECTION INPUT ;
    USE SIGNAL ;
    SHAPE ABUTMENT ;
    PORT
      LAYER metal3 ;
      RECT 0.000 515.200 0.140 515.340 ;
    END
  END w_mask_in[183]
  PIN addr_in[0]
    DIRECTION INPUT ;
    USE SIGNAL ;
    SHAPE ABUTMENT ;
    PORT
      LAYER metal3 ;
      RECT 0.000 516.600 0.140 516.740 ;
    END
  END addr_in[0]
  PIN addr_in[1]
    DIRECTION INPUT ;
    USE SIGNAL ;
    SHAPE ABUTMENT ;
    PORT
      LAYER metal3 ;
      RECT 0.000 518.000 0.140 518.140 ;
    END
  END addr_in[1]
  PIN addr_in[2]
    DIRECTION INPUT ;
    USE SIGNAL ;
    SHAPE ABUTMENT ;
    PORT
      LAYER metal3 ;
      RECT 0.000 519.400 0.140 519.540 ;
    END
  END addr_in[2]
  PIN addr_in[3]
    DIRECTION INPUT ;
    USE SIGNAL ;
    SHAPE ABUTMENT ;
    PORT
      LAYER metal3 ;
      RECT 0.000 520.800 0.140 520.940 ;
    END
  END addr_in[3]
  PIN addr_in[4]
    DIRECTION INPUT ;
    USE SIGNAL ;
    SHAPE ABUTMENT ;
    PORT
      LAYER metal3 ;
      RECT 0.000 522.200 0.140 522.340 ;
    END
  END addr_in[4]
  PIN addr_in[5]
    DIRECTION INPUT ;
    USE SIGNAL ;
    SHAPE ABUTMENT ;
    PORT
      LAYER metal3 ;
      RECT 0.000 523.600 0.140 523.740 ;
    END
  END addr_in[5]
  PIN rd_out[0]
    DIRECTION OUTPUT ;
    USE SIGNAL ;
    SHAPE ABUTMENT ;
    PORT
      LAYER metal3 ;
      RECT 0.000 525.000 0.140 525.140 ;
    END
  END rd_out[0]
  PIN rd_out[1]
    DIRECTION OUTPUT ;
    USE SIGNAL ;
    SHAPE ABUTMENT ;
    PORT
      LAYER metal3 ;
      RECT 0.000 526.400 0.140 526.540 ;
    END
  END rd_out[1]
  PIN rd_out[2]
    DIRECTION OUTPUT ;
    USE SIGNAL ;
    SHAPE ABUTMENT ;
    PORT
      LAYER metal3 ;
      RECT 0.000 527.800 0.140 527.940 ;
    END
  END rd_out[2]
  PIN rd_out[3]
    DIRECTION OUTPUT ;
    USE SIGNAL ;
    SHAPE ABUTMENT ;
    PORT
      LAYER metal3 ;
      RECT 0.000 529.200 0.140 529.340 ;
    END
  END rd_out[3]
  PIN rd_out[4]
    DIRECTION OUTPUT ;
    USE SIGNAL ;
    SHAPE ABUTMENT ;
    PORT
      LAYER metal3 ;
      RECT 0.000 530.600 0.140 530.740 ;
    END
  END rd_out[4]
  PIN rd_out[5]
    DIRECTION OUTPUT ;
    USE SIGNAL ;
    SHAPE ABUTMENT ;
    PORT
      LAYER metal3 ;
      RECT 0.000 532.000 0.140 532.140 ;
    END
  END rd_out[5]
  PIN rd_out[6]
    DIRECTION OUTPUT ;
    USE SIGNAL ;
    SHAPE ABUTMENT ;
    PORT
      LAYER metal3 ;
      RECT 0.000 533.400 0.140 533.540 ;
    END
  END rd_out[6]
  PIN rd_out[7]
    DIRECTION OUTPUT ;
    USE SIGNAL ;
    SHAPE ABUTMENT ;
    PORT
      LAYER metal3 ;
      RECT 0.000 534.800 0.140 534.940 ;
    END
  END rd_out[7]
  PIN rd_out[8]
    DIRECTION OUTPUT ;
    USE SIGNAL ;
    SHAPE ABUTMENT ;
    PORT
      LAYER metal3 ;
      RECT 0.000 536.200 0.140 536.340 ;
    END
  END rd_out[8]
  PIN rd_out[9]
    DIRECTION OUTPUT ;
    USE SIGNAL ;
    SHAPE ABUTMENT ;
    PORT
      LAYER metal3 ;
      RECT 0.000 537.600 0.140 537.740 ;
    END
  END rd_out[9]
  PIN rd_out[10]
    DIRECTION OUTPUT ;
    USE SIGNAL ;
    SHAPE ABUTMENT ;
    PORT
      LAYER metal3 ;
      RECT 0.000 539.000 0.140 539.140 ;
    END
  END rd_out[10]
  PIN rd_out[11]
    DIRECTION OUTPUT ;
    USE SIGNAL ;
    SHAPE ABUTMENT ;
    PORT
      LAYER metal3 ;
      RECT 0.000 540.400 0.140 540.540 ;
    END
  END rd_out[11]
  PIN rd_out[12]
    DIRECTION OUTPUT ;
    USE SIGNAL ;
    SHAPE ABUTMENT ;
    PORT
      LAYER metal3 ;
      RECT 0.000 541.800 0.140 541.940 ;
    END
  END rd_out[12]
  PIN rd_out[13]
    DIRECTION OUTPUT ;
    USE SIGNAL ;
    SHAPE ABUTMENT ;
    PORT
      LAYER metal3 ;
      RECT 0.000 543.200 0.140 543.340 ;
    END
  END rd_out[13]
  PIN rd_out[14]
    DIRECTION OUTPUT ;
    USE SIGNAL ;
    SHAPE ABUTMENT ;
    PORT
      LAYER metal3 ;
      RECT 0.000 544.600 0.140 544.740 ;
    END
  END rd_out[14]
  PIN rd_out[15]
    DIRECTION OUTPUT ;
    USE SIGNAL ;
    SHAPE ABUTMENT ;
    PORT
      LAYER metal3 ;
      RECT 0.000 546.000 0.140 546.140 ;
    END
  END rd_out[15]
  PIN rd_out[16]
    DIRECTION OUTPUT ;
    USE SIGNAL ;
    SHAPE ABUTMENT ;
    PORT
      LAYER metal3 ;
      RECT 0.000 547.400 0.140 547.540 ;
    END
  END rd_out[16]
  PIN rd_out[17]
    DIRECTION OUTPUT ;
    USE SIGNAL ;
    SHAPE ABUTMENT ;
    PORT
      LAYER metal3 ;
      RECT 0.000 548.800 0.140 548.940 ;
    END
  END rd_out[17]
  PIN rd_out[18]
    DIRECTION OUTPUT ;
    USE SIGNAL ;
    SHAPE ABUTMENT ;
    PORT
      LAYER metal3 ;
      RECT 0.000 550.200 0.140 550.340 ;
    END
  END rd_out[18]
  PIN rd_out[19]
    DIRECTION OUTPUT ;
    USE SIGNAL ;
    SHAPE ABUTMENT ;
    PORT
      LAYER metal3 ;
      RECT 0.000 551.600 0.140 551.740 ;
    END
  END rd_out[19]
  PIN rd_out[20]
    DIRECTION OUTPUT ;
    USE SIGNAL ;
    SHAPE ABUTMENT ;
    PORT
      LAYER metal3 ;
      RECT 0.000 553.000 0.140 553.140 ;
    END
  END rd_out[20]
  PIN rd_out[21]
    DIRECTION OUTPUT ;
    USE SIGNAL ;
    SHAPE ABUTMENT ;
    PORT
      LAYER metal3 ;
      RECT 0.000 554.400 0.140 554.540 ;
    END
  END rd_out[21]
  PIN rd_out[22]
    DIRECTION OUTPUT ;
    USE SIGNAL ;
    SHAPE ABUTMENT ;
    PORT
      LAYER metal3 ;
      RECT 0.000 555.800 0.140 555.940 ;
    END
  END rd_out[22]
  PIN rd_out[23]
    DIRECTION OUTPUT ;
    USE SIGNAL ;
    SHAPE ABUTMENT ;
    PORT
      LAYER metal3 ;
      RECT 0.000 557.200 0.140 557.340 ;
    END
  END rd_out[23]
  PIN rd_out[24]
    DIRECTION OUTPUT ;
    USE SIGNAL ;
    SHAPE ABUTMENT ;
    PORT
      LAYER metal3 ;
      RECT 0.000 558.600 0.140 558.740 ;
    END
  END rd_out[24]
  PIN rd_out[25]
    DIRECTION OUTPUT ;
    USE SIGNAL ;
    SHAPE ABUTMENT ;
    PORT
      LAYER metal3 ;
      RECT 0.000 560.000 0.140 560.140 ;
    END
  END rd_out[25]
  PIN rd_out[26]
    DIRECTION OUTPUT ;
    USE SIGNAL ;
    SHAPE ABUTMENT ;
    PORT
      LAYER metal3 ;
      RECT 0.000 561.400 0.140 561.540 ;
    END
  END rd_out[26]
  PIN rd_out[27]
    DIRECTION OUTPUT ;
    USE SIGNAL ;
    SHAPE ABUTMENT ;
    PORT
      LAYER metal3 ;
      RECT 0.000 562.800 0.140 562.940 ;
    END
  END rd_out[27]
  PIN rd_out[28]
    DIRECTION OUTPUT ;
    USE SIGNAL ;
    SHAPE ABUTMENT ;
    PORT
      LAYER metal3 ;
      RECT 0.000 564.200 0.140 564.340 ;
    END
  END rd_out[28]
  PIN rd_out[29]
    DIRECTION OUTPUT ;
    USE SIGNAL ;
    SHAPE ABUTMENT ;
    PORT
      LAYER metal3 ;
      RECT 0.000 565.600 0.140 565.740 ;
    END
  END rd_out[29]
  PIN rd_out[30]
    DIRECTION OUTPUT ;
    USE SIGNAL ;
    SHAPE ABUTMENT ;
    PORT
      LAYER metal3 ;
      RECT 0.000 567.000 0.140 567.140 ;
    END
  END rd_out[30]
  PIN rd_out[31]
    DIRECTION OUTPUT ;
    USE SIGNAL ;
    SHAPE ABUTMENT ;
    PORT
      LAYER metal3 ;
      RECT 0.000 568.400 0.140 568.540 ;
    END
  END rd_out[31]
  PIN rd_out[32]
    DIRECTION OUTPUT ;
    USE SIGNAL ;
    SHAPE ABUTMENT ;
    PORT
      LAYER metal3 ;
      RECT 0.000 569.800 0.140 569.940 ;
    END
  END rd_out[32]
  PIN rd_out[33]
    DIRECTION OUTPUT ;
    USE SIGNAL ;
    SHAPE ABUTMENT ;
    PORT
      LAYER metal3 ;
      RECT 0.000 571.200 0.140 571.340 ;
    END
  END rd_out[33]
  PIN rd_out[34]
    DIRECTION OUTPUT ;
    USE SIGNAL ;
    SHAPE ABUTMENT ;
    PORT
      LAYER metal3 ;
      RECT 0.000 572.600 0.140 572.740 ;
    END
  END rd_out[34]
  PIN rd_out[35]
    DIRECTION OUTPUT ;
    USE SIGNAL ;
    SHAPE ABUTMENT ;
    PORT
      LAYER metal3 ;
      RECT 0.000 574.000 0.140 574.140 ;
    END
  END rd_out[35]
  PIN rd_out[36]
    DIRECTION OUTPUT ;
    USE SIGNAL ;
    SHAPE ABUTMENT ;
    PORT
      LAYER metal3 ;
      RECT 0.000 575.400 0.140 575.540 ;
    END
  END rd_out[36]
  PIN rd_out[37]
    DIRECTION OUTPUT ;
    USE SIGNAL ;
    SHAPE ABUTMENT ;
    PORT
      LAYER metal3 ;
      RECT 0.000 576.800 0.140 576.940 ;
    END
  END rd_out[37]
  PIN rd_out[38]
    DIRECTION OUTPUT ;
    USE SIGNAL ;
    SHAPE ABUTMENT ;
    PORT
      LAYER metal3 ;
      RECT 0.000 578.200 0.140 578.340 ;
    END
  END rd_out[38]
  PIN rd_out[39]
    DIRECTION OUTPUT ;
    USE SIGNAL ;
    SHAPE ABUTMENT ;
    PORT
      LAYER metal3 ;
      RECT 0.000 579.600 0.140 579.740 ;
    END
  END rd_out[39]
  PIN rd_out[40]
    DIRECTION OUTPUT ;
    USE SIGNAL ;
    SHAPE ABUTMENT ;
    PORT
      LAYER metal3 ;
      RECT 0.000 581.000 0.140 581.140 ;
    END
  END rd_out[40]
  PIN rd_out[41]
    DIRECTION OUTPUT ;
    USE SIGNAL ;
    SHAPE ABUTMENT ;
    PORT
      LAYER metal3 ;
      RECT 0.000 582.400 0.140 582.540 ;
    END
  END rd_out[41]
  PIN rd_out[42]
    DIRECTION OUTPUT ;
    USE SIGNAL ;
    SHAPE ABUTMENT ;
    PORT
      LAYER metal3 ;
      RECT 0.000 583.800 0.140 583.940 ;
    END
  END rd_out[42]
  PIN rd_out[43]
    DIRECTION OUTPUT ;
    USE SIGNAL ;
    SHAPE ABUTMENT ;
    PORT
      LAYER metal3 ;
      RECT 0.000 585.200 0.140 585.340 ;
    END
  END rd_out[43]
  PIN rd_out[44]
    DIRECTION OUTPUT ;
    USE SIGNAL ;
    SHAPE ABUTMENT ;
    PORT
      LAYER metal3 ;
      RECT 0.000 586.600 0.140 586.740 ;
    END
  END rd_out[44]
  PIN rd_out[45]
    DIRECTION OUTPUT ;
    USE SIGNAL ;
    SHAPE ABUTMENT ;
    PORT
      LAYER metal3 ;
      RECT 0.000 588.000 0.140 588.140 ;
    END
  END rd_out[45]
  PIN rd_out[46]
    DIRECTION OUTPUT ;
    USE SIGNAL ;
    SHAPE ABUTMENT ;
    PORT
      LAYER metal3 ;
      RECT 0.000 589.400 0.140 589.540 ;
    END
  END rd_out[46]
  PIN rd_out[47]
    DIRECTION OUTPUT ;
    USE SIGNAL ;
    SHAPE ABUTMENT ;
    PORT
      LAYER metal3 ;
      RECT 0.000 590.800 0.140 590.940 ;
    END
  END rd_out[47]
  PIN rd_out[48]
    DIRECTION OUTPUT ;
    USE SIGNAL ;
    SHAPE ABUTMENT ;
    PORT
      LAYER metal3 ;
      RECT 0.000 592.200 0.140 592.340 ;
    END
  END rd_out[48]
  PIN rd_out[49]
    DIRECTION OUTPUT ;
    USE SIGNAL ;
    SHAPE ABUTMENT ;
    PORT
      LAYER metal3 ;
      RECT 0.000 593.600 0.140 593.740 ;
    END
  END rd_out[49]
  PIN rd_out[50]
    DIRECTION OUTPUT ;
    USE SIGNAL ;
    SHAPE ABUTMENT ;
    PORT
      LAYER metal3 ;
      RECT 0.000 595.000 0.140 595.140 ;
    END
  END rd_out[50]
  PIN rd_out[51]
    DIRECTION OUTPUT ;
    USE SIGNAL ;
    SHAPE ABUTMENT ;
    PORT
      LAYER metal3 ;
      RECT 0.000 596.400 0.140 596.540 ;
    END
  END rd_out[51]
  PIN rd_out[52]
    DIRECTION OUTPUT ;
    USE SIGNAL ;
    SHAPE ABUTMENT ;
    PORT
      LAYER metal3 ;
      RECT 0.000 597.800 0.140 597.940 ;
    END
  END rd_out[52]
  PIN rd_out[53]
    DIRECTION OUTPUT ;
    USE SIGNAL ;
    SHAPE ABUTMENT ;
    PORT
      LAYER metal3 ;
      RECT 0.000 599.200 0.140 599.340 ;
    END
  END rd_out[53]
  PIN rd_out[54]
    DIRECTION OUTPUT ;
    USE SIGNAL ;
    SHAPE ABUTMENT ;
    PORT
      LAYER metal3 ;
      RECT 0.000 600.600 0.140 600.740 ;
    END
  END rd_out[54]
  PIN rd_out[55]
    DIRECTION OUTPUT ;
    USE SIGNAL ;
    SHAPE ABUTMENT ;
    PORT
      LAYER metal3 ;
      RECT 0.000 602.000 0.140 602.140 ;
    END
  END rd_out[55]
  PIN rd_out[56]
    DIRECTION OUTPUT ;
    USE SIGNAL ;
    SHAPE ABUTMENT ;
    PORT
      LAYER metal3 ;
      RECT 0.000 603.400 0.140 603.540 ;
    END
  END rd_out[56]
  PIN rd_out[57]
    DIRECTION OUTPUT ;
    USE SIGNAL ;
    SHAPE ABUTMENT ;
    PORT
      LAYER metal3 ;
      RECT 0.000 604.800 0.140 604.940 ;
    END
  END rd_out[57]
  PIN rd_out[58]
    DIRECTION OUTPUT ;
    USE SIGNAL ;
    SHAPE ABUTMENT ;
    PORT
      LAYER metal3 ;
      RECT 0.000 606.200 0.140 606.340 ;
    END
  END rd_out[58]
  PIN rd_out[59]
    DIRECTION OUTPUT ;
    USE SIGNAL ;
    SHAPE ABUTMENT ;
    PORT
      LAYER metal3 ;
      RECT 0.000 607.600 0.140 607.740 ;
    END
  END rd_out[59]
  PIN rd_out[60]
    DIRECTION OUTPUT ;
    USE SIGNAL ;
    SHAPE ABUTMENT ;
    PORT
      LAYER metal3 ;
      RECT 0.000 609.000 0.140 609.140 ;
    END
  END rd_out[60]
  PIN rd_out[61]
    DIRECTION OUTPUT ;
    USE SIGNAL ;
    SHAPE ABUTMENT ;
    PORT
      LAYER metal3 ;
      RECT 0.000 610.400 0.140 610.540 ;
    END
  END rd_out[61]
  PIN rd_out[62]
    DIRECTION OUTPUT ;
    USE SIGNAL ;
    SHAPE ABUTMENT ;
    PORT
      LAYER metal3 ;
      RECT 0.000 611.800 0.140 611.940 ;
    END
  END rd_out[62]
  PIN rd_out[63]
    DIRECTION OUTPUT ;
    USE SIGNAL ;
    SHAPE ABUTMENT ;
    PORT
      LAYER metal3 ;
      RECT 0.000 613.200 0.140 613.340 ;
    END
  END rd_out[63]
  PIN rd_out[64]
    DIRECTION OUTPUT ;
    USE SIGNAL ;
    SHAPE ABUTMENT ;
    PORT
      LAYER metal3 ;
      RECT 0.000 614.600 0.140 614.740 ;
    END
  END rd_out[64]
  PIN rd_out[65]
    DIRECTION OUTPUT ;
    USE SIGNAL ;
    SHAPE ABUTMENT ;
    PORT
      LAYER metal3 ;
      RECT 0.000 616.000 0.140 616.140 ;
    END
  END rd_out[65]
  PIN rd_out[66]
    DIRECTION OUTPUT ;
    USE SIGNAL ;
    SHAPE ABUTMENT ;
    PORT
      LAYER metal3 ;
      RECT 0.000 617.400 0.140 617.540 ;
    END
  END rd_out[66]
  PIN rd_out[67]
    DIRECTION OUTPUT ;
    USE SIGNAL ;
    SHAPE ABUTMENT ;
    PORT
      LAYER metal3 ;
      RECT 0.000 618.800 0.140 618.940 ;
    END
  END rd_out[67]
  PIN rd_out[68]
    DIRECTION OUTPUT ;
    USE SIGNAL ;
    SHAPE ABUTMENT ;
    PORT
      LAYER metal3 ;
      RECT 0.000 620.200 0.140 620.340 ;
    END
  END rd_out[68]
  PIN rd_out[69]
    DIRECTION OUTPUT ;
    USE SIGNAL ;
    SHAPE ABUTMENT ;
    PORT
      LAYER metal3 ;
      RECT 0.000 621.600 0.140 621.740 ;
    END
  END rd_out[69]
  PIN rd_out[70]
    DIRECTION OUTPUT ;
    USE SIGNAL ;
    SHAPE ABUTMENT ;
    PORT
      LAYER metal3 ;
      RECT 0.000 623.000 0.140 623.140 ;
    END
  END rd_out[70]
  PIN rd_out[71]
    DIRECTION OUTPUT ;
    USE SIGNAL ;
    SHAPE ABUTMENT ;
    PORT
      LAYER metal3 ;
      RECT 0.000 624.400 0.140 624.540 ;
    END
  END rd_out[71]
  PIN rd_out[72]
    DIRECTION OUTPUT ;
    USE SIGNAL ;
    SHAPE ABUTMENT ;
    PORT
      LAYER metal3 ;
      RECT 0.000 625.800 0.140 625.940 ;
    END
  END rd_out[72]
  PIN rd_out[73]
    DIRECTION OUTPUT ;
    USE SIGNAL ;
    SHAPE ABUTMENT ;
    PORT
      LAYER metal3 ;
      RECT 0.000 627.200 0.140 627.340 ;
    END
  END rd_out[73]
  PIN rd_out[74]
    DIRECTION OUTPUT ;
    USE SIGNAL ;
    SHAPE ABUTMENT ;
    PORT
      LAYER metal3 ;
      RECT 0.000 628.600 0.140 628.740 ;
    END
  END rd_out[74]
  PIN rd_out[75]
    DIRECTION OUTPUT ;
    USE SIGNAL ;
    SHAPE ABUTMENT ;
    PORT
      LAYER metal3 ;
      RECT 0.000 630.000 0.140 630.140 ;
    END
  END rd_out[75]
  PIN rd_out[76]
    DIRECTION OUTPUT ;
    USE SIGNAL ;
    SHAPE ABUTMENT ;
    PORT
      LAYER metal3 ;
      RECT 0.000 631.400 0.140 631.540 ;
    END
  END rd_out[76]
  PIN rd_out[77]
    DIRECTION OUTPUT ;
    USE SIGNAL ;
    SHAPE ABUTMENT ;
    PORT
      LAYER metal3 ;
      RECT 0.000 632.800 0.140 632.940 ;
    END
  END rd_out[77]
  PIN rd_out[78]
    DIRECTION OUTPUT ;
    USE SIGNAL ;
    SHAPE ABUTMENT ;
    PORT
      LAYER metal3 ;
      RECT 0.000 634.200 0.140 634.340 ;
    END
  END rd_out[78]
  PIN rd_out[79]
    DIRECTION OUTPUT ;
    USE SIGNAL ;
    SHAPE ABUTMENT ;
    PORT
      LAYER metal3 ;
      RECT 0.000 635.600 0.140 635.740 ;
    END
  END rd_out[79]
  PIN rd_out[80]
    DIRECTION OUTPUT ;
    USE SIGNAL ;
    SHAPE ABUTMENT ;
    PORT
      LAYER metal3 ;
      RECT 0.000 637.000 0.140 637.140 ;
    END
  END rd_out[80]
  PIN rd_out[81]
    DIRECTION OUTPUT ;
    USE SIGNAL ;
    SHAPE ABUTMENT ;
    PORT
      LAYER metal3 ;
      RECT 0.000 638.400 0.140 638.540 ;
    END
  END rd_out[81]
  PIN rd_out[82]
    DIRECTION OUTPUT ;
    USE SIGNAL ;
    SHAPE ABUTMENT ;
    PORT
      LAYER metal3 ;
      RECT 0.000 639.800 0.140 639.940 ;
    END
  END rd_out[82]
  PIN rd_out[83]
    DIRECTION OUTPUT ;
    USE SIGNAL ;
    SHAPE ABUTMENT ;
    PORT
      LAYER metal3 ;
      RECT 0.000 641.200 0.140 641.340 ;
    END
  END rd_out[83]
  PIN rd_out[84]
    DIRECTION OUTPUT ;
    USE SIGNAL ;
    SHAPE ABUTMENT ;
    PORT
      LAYER metal3 ;
      RECT 0.000 642.600 0.140 642.740 ;
    END
  END rd_out[84]
  PIN rd_out[85]
    DIRECTION OUTPUT ;
    USE SIGNAL ;
    SHAPE ABUTMENT ;
    PORT
      LAYER metal3 ;
      RECT 0.000 644.000 0.140 644.140 ;
    END
  END rd_out[85]
  PIN rd_out[86]
    DIRECTION OUTPUT ;
    USE SIGNAL ;
    SHAPE ABUTMENT ;
    PORT
      LAYER metal3 ;
      RECT 0.000 645.400 0.140 645.540 ;
    END
  END rd_out[86]
  PIN rd_out[87]
    DIRECTION OUTPUT ;
    USE SIGNAL ;
    SHAPE ABUTMENT ;
    PORT
      LAYER metal3 ;
      RECT 0.000 646.800 0.140 646.940 ;
    END
  END rd_out[87]
  PIN rd_out[88]
    DIRECTION OUTPUT ;
    USE SIGNAL ;
    SHAPE ABUTMENT ;
    PORT
      LAYER metal3 ;
      RECT 0.000 648.200 0.140 648.340 ;
    END
  END rd_out[88]
  PIN rd_out[89]
    DIRECTION OUTPUT ;
    USE SIGNAL ;
    SHAPE ABUTMENT ;
    PORT
      LAYER metal3 ;
      RECT 0.000 649.600 0.140 649.740 ;
    END
  END rd_out[89]
  PIN rd_out[90]
    DIRECTION OUTPUT ;
    USE SIGNAL ;
    SHAPE ABUTMENT ;
    PORT
      LAYER metal3 ;
      RECT 0.000 651.000 0.140 651.140 ;
    END
  END rd_out[90]
  PIN rd_out[91]
    DIRECTION OUTPUT ;
    USE SIGNAL ;
    SHAPE ABUTMENT ;
    PORT
      LAYER metal3 ;
      RECT 0.000 652.400 0.140 652.540 ;
    END
  END rd_out[91]
  PIN rd_out[92]
    DIRECTION OUTPUT ;
    USE SIGNAL ;
    SHAPE ABUTMENT ;
    PORT
      LAYER metal3 ;
      RECT 0.000 653.800 0.140 653.940 ;
    END
  END rd_out[92]
  PIN rd_out[93]
    DIRECTION OUTPUT ;
    USE SIGNAL ;
    SHAPE ABUTMENT ;
    PORT
      LAYER metal3 ;
      RECT 0.000 655.200 0.140 655.340 ;
    END
  END rd_out[93]
  PIN rd_out[94]
    DIRECTION OUTPUT ;
    USE SIGNAL ;
    SHAPE ABUTMENT ;
    PORT
      LAYER metal3 ;
      RECT 0.000 656.600 0.140 656.740 ;
    END
  END rd_out[94]
  PIN rd_out[95]
    DIRECTION OUTPUT ;
    USE SIGNAL ;
    SHAPE ABUTMENT ;
    PORT
      LAYER metal3 ;
      RECT 0.000 658.000 0.140 658.140 ;
    END
  END rd_out[95]
  PIN rd_out[96]
    DIRECTION OUTPUT ;
    USE SIGNAL ;
    SHAPE ABUTMENT ;
    PORT
      LAYER metal3 ;
      RECT 0.000 659.400 0.140 659.540 ;
    END
  END rd_out[96]
  PIN rd_out[97]
    DIRECTION OUTPUT ;
    USE SIGNAL ;
    SHAPE ABUTMENT ;
    PORT
      LAYER metal3 ;
      RECT 0.000 660.800 0.140 660.940 ;
    END
  END rd_out[97]
  PIN rd_out[98]
    DIRECTION OUTPUT ;
    USE SIGNAL ;
    SHAPE ABUTMENT ;
    PORT
      LAYER metal3 ;
      RECT 0.000 662.200 0.140 662.340 ;
    END
  END rd_out[98]
  PIN rd_out[99]
    DIRECTION OUTPUT ;
    USE SIGNAL ;
    SHAPE ABUTMENT ;
    PORT
      LAYER metal3 ;
      RECT 0.000 663.600 0.140 663.740 ;
    END
  END rd_out[99]
  PIN rd_out[100]
    DIRECTION OUTPUT ;
    USE SIGNAL ;
    SHAPE ABUTMENT ;
    PORT
      LAYER metal3 ;
      RECT 0.000 665.000 0.140 665.140 ;
    END
  END rd_out[100]
  PIN rd_out[101]
    DIRECTION OUTPUT ;
    USE SIGNAL ;
    SHAPE ABUTMENT ;
    PORT
      LAYER metal3 ;
      RECT 0.000 666.400 0.140 666.540 ;
    END
  END rd_out[101]
  PIN rd_out[102]
    DIRECTION OUTPUT ;
    USE SIGNAL ;
    SHAPE ABUTMENT ;
    PORT
      LAYER metal3 ;
      RECT 0.000 667.800 0.140 667.940 ;
    END
  END rd_out[102]
  PIN rd_out[103]
    DIRECTION OUTPUT ;
    USE SIGNAL ;
    SHAPE ABUTMENT ;
    PORT
      LAYER metal3 ;
      RECT 0.000 669.200 0.140 669.340 ;
    END
  END rd_out[103]
  PIN rd_out[104]
    DIRECTION OUTPUT ;
    USE SIGNAL ;
    SHAPE ABUTMENT ;
    PORT
      LAYER metal3 ;
      RECT 0.000 670.600 0.140 670.740 ;
    END
  END rd_out[104]
  PIN rd_out[105]
    DIRECTION OUTPUT ;
    USE SIGNAL ;
    SHAPE ABUTMENT ;
    PORT
      LAYER metal3 ;
      RECT 0.000 672.000 0.140 672.140 ;
    END
  END rd_out[105]
  PIN rd_out[106]
    DIRECTION OUTPUT ;
    USE SIGNAL ;
    SHAPE ABUTMENT ;
    PORT
      LAYER metal3 ;
      RECT 0.000 673.400 0.140 673.540 ;
    END
  END rd_out[106]
  PIN rd_out[107]
    DIRECTION OUTPUT ;
    USE SIGNAL ;
    SHAPE ABUTMENT ;
    PORT
      LAYER metal3 ;
      RECT 0.000 674.800 0.140 674.940 ;
    END
  END rd_out[107]
  PIN rd_out[108]
    DIRECTION OUTPUT ;
    USE SIGNAL ;
    SHAPE ABUTMENT ;
    PORT
      LAYER metal3 ;
      RECT 0.000 676.200 0.140 676.340 ;
    END
  END rd_out[108]
  PIN rd_out[109]
    DIRECTION OUTPUT ;
    USE SIGNAL ;
    SHAPE ABUTMENT ;
    PORT
      LAYER metal3 ;
      RECT 0.000 677.600 0.140 677.740 ;
    END
  END rd_out[109]
  PIN rd_out[110]
    DIRECTION OUTPUT ;
    USE SIGNAL ;
    SHAPE ABUTMENT ;
    PORT
      LAYER metal3 ;
      RECT 0.000 679.000 0.140 679.140 ;
    END
  END rd_out[110]
  PIN rd_out[111]
    DIRECTION OUTPUT ;
    USE SIGNAL ;
    SHAPE ABUTMENT ;
    PORT
      LAYER metal3 ;
      RECT 0.000 680.400 0.140 680.540 ;
    END
  END rd_out[111]
  PIN rd_out[112]
    DIRECTION OUTPUT ;
    USE SIGNAL ;
    SHAPE ABUTMENT ;
    PORT
      LAYER metal3 ;
      RECT 0.000 681.800 0.140 681.940 ;
    END
  END rd_out[112]
  PIN rd_out[113]
    DIRECTION OUTPUT ;
    USE SIGNAL ;
    SHAPE ABUTMENT ;
    PORT
      LAYER metal3 ;
      RECT 0.000 683.200 0.140 683.340 ;
    END
  END rd_out[113]
  PIN rd_out[114]
    DIRECTION OUTPUT ;
    USE SIGNAL ;
    SHAPE ABUTMENT ;
    PORT
      LAYER metal3 ;
      RECT 0.000 684.600 0.140 684.740 ;
    END
  END rd_out[114]
  PIN rd_out[115]
    DIRECTION OUTPUT ;
    USE SIGNAL ;
    SHAPE ABUTMENT ;
    PORT
      LAYER metal3 ;
      RECT 0.000 686.000 0.140 686.140 ;
    END
  END rd_out[115]
  PIN rd_out[116]
    DIRECTION OUTPUT ;
    USE SIGNAL ;
    SHAPE ABUTMENT ;
    PORT
      LAYER metal3 ;
      RECT 0.000 687.400 0.140 687.540 ;
    END
  END rd_out[116]
  PIN rd_out[117]
    DIRECTION OUTPUT ;
    USE SIGNAL ;
    SHAPE ABUTMENT ;
    PORT
      LAYER metal3 ;
      RECT 0.000 688.800 0.140 688.940 ;
    END
  END rd_out[117]
  PIN rd_out[118]
    DIRECTION OUTPUT ;
    USE SIGNAL ;
    SHAPE ABUTMENT ;
    PORT
      LAYER metal3 ;
      RECT 0.000 690.200 0.140 690.340 ;
    END
  END rd_out[118]
  PIN rd_out[119]
    DIRECTION OUTPUT ;
    USE SIGNAL ;
    SHAPE ABUTMENT ;
    PORT
      LAYER metal3 ;
      RECT 0.000 691.600 0.140 691.740 ;
    END
  END rd_out[119]
  PIN rd_out[120]
    DIRECTION OUTPUT ;
    USE SIGNAL ;
    SHAPE ABUTMENT ;
    PORT
      LAYER metal3 ;
      RECT 0.000 693.000 0.140 693.140 ;
    END
  END rd_out[120]
  PIN rd_out[121]
    DIRECTION OUTPUT ;
    USE SIGNAL ;
    SHAPE ABUTMENT ;
    PORT
      LAYER metal3 ;
      RECT 0.000 694.400 0.140 694.540 ;
    END
  END rd_out[121]
  PIN rd_out[122]
    DIRECTION OUTPUT ;
    USE SIGNAL ;
    SHAPE ABUTMENT ;
    PORT
      LAYER metal3 ;
      RECT 0.000 695.800 0.140 695.940 ;
    END
  END rd_out[122]
  PIN rd_out[123]
    DIRECTION OUTPUT ;
    USE SIGNAL ;
    SHAPE ABUTMENT ;
    PORT
      LAYER metal3 ;
      RECT 0.000 697.200 0.140 697.340 ;
    END
  END rd_out[123]
  PIN rd_out[124]
    DIRECTION OUTPUT ;
    USE SIGNAL ;
    SHAPE ABUTMENT ;
    PORT
      LAYER metal3 ;
      RECT 0.000 698.600 0.140 698.740 ;
    END
  END rd_out[124]
  PIN rd_out[125]
    DIRECTION OUTPUT ;
    USE SIGNAL ;
    SHAPE ABUTMENT ;
    PORT
      LAYER metal3 ;
      RECT 0.000 700.000 0.140 700.140 ;
    END
  END rd_out[125]
  PIN rd_out[126]
    DIRECTION OUTPUT ;
    USE SIGNAL ;
    SHAPE ABUTMENT ;
    PORT
      LAYER metal3 ;
      RECT 0.000 701.400 0.140 701.540 ;
    END
  END rd_out[126]
  PIN rd_out[127]
    DIRECTION OUTPUT ;
    USE SIGNAL ;
    SHAPE ABUTMENT ;
    PORT
      LAYER metal3 ;
      RECT 0.000 702.800 0.140 702.940 ;
    END
  END rd_out[127]
  PIN rd_out[128]
    DIRECTION OUTPUT ;
    USE SIGNAL ;
    SHAPE ABUTMENT ;
    PORT
      LAYER metal3 ;
      RECT 0.000 704.200 0.140 704.340 ;
    END
  END rd_out[128]
  PIN rd_out[129]
    DIRECTION OUTPUT ;
    USE SIGNAL ;
    SHAPE ABUTMENT ;
    PORT
      LAYER metal3 ;
      RECT 0.000 705.600 0.140 705.740 ;
    END
  END rd_out[129]
  PIN rd_out[130]
    DIRECTION OUTPUT ;
    USE SIGNAL ;
    SHAPE ABUTMENT ;
    PORT
      LAYER metal3 ;
      RECT 0.000 707.000 0.140 707.140 ;
    END
  END rd_out[130]
  PIN rd_out[131]
    DIRECTION OUTPUT ;
    USE SIGNAL ;
    SHAPE ABUTMENT ;
    PORT
      LAYER metal3 ;
      RECT 0.000 708.400 0.140 708.540 ;
    END
  END rd_out[131]
  PIN rd_out[132]
    DIRECTION OUTPUT ;
    USE SIGNAL ;
    SHAPE ABUTMENT ;
    PORT
      LAYER metal3 ;
      RECT 0.000 709.800 0.140 709.940 ;
    END
  END rd_out[132]
  PIN rd_out[133]
    DIRECTION OUTPUT ;
    USE SIGNAL ;
    SHAPE ABUTMENT ;
    PORT
      LAYER metal3 ;
      RECT 0.000 711.200 0.140 711.340 ;
    END
  END rd_out[133]
  PIN rd_out[134]
    DIRECTION OUTPUT ;
    USE SIGNAL ;
    SHAPE ABUTMENT ;
    PORT
      LAYER metal3 ;
      RECT 0.000 712.600 0.140 712.740 ;
    END
  END rd_out[134]
  PIN rd_out[135]
    DIRECTION OUTPUT ;
    USE SIGNAL ;
    SHAPE ABUTMENT ;
    PORT
      LAYER metal3 ;
      RECT 0.000 714.000 0.140 714.140 ;
    END
  END rd_out[135]
  PIN rd_out[136]
    DIRECTION OUTPUT ;
    USE SIGNAL ;
    SHAPE ABUTMENT ;
    PORT
      LAYER metal3 ;
      RECT 0.000 715.400 0.140 715.540 ;
    END
  END rd_out[136]
  PIN rd_out[137]
    DIRECTION OUTPUT ;
    USE SIGNAL ;
    SHAPE ABUTMENT ;
    PORT
      LAYER metal3 ;
      RECT 0.000 716.800 0.140 716.940 ;
    END
  END rd_out[137]
  PIN rd_out[138]
    DIRECTION OUTPUT ;
    USE SIGNAL ;
    SHAPE ABUTMENT ;
    PORT
      LAYER metal3 ;
      RECT 0.000 718.200 0.140 718.340 ;
    END
  END rd_out[138]
  PIN rd_out[139]
    DIRECTION OUTPUT ;
    USE SIGNAL ;
    SHAPE ABUTMENT ;
    PORT
      LAYER metal3 ;
      RECT 0.000 719.600 0.140 719.740 ;
    END
  END rd_out[139]
  PIN rd_out[140]
    DIRECTION OUTPUT ;
    USE SIGNAL ;
    SHAPE ABUTMENT ;
    PORT
      LAYER metal3 ;
      RECT 0.000 721.000 0.140 721.140 ;
    END
  END rd_out[140]
  PIN rd_out[141]
    DIRECTION OUTPUT ;
    USE SIGNAL ;
    SHAPE ABUTMENT ;
    PORT
      LAYER metal3 ;
      RECT 0.000 722.400 0.140 722.540 ;
    END
  END rd_out[141]
  PIN rd_out[142]
    DIRECTION OUTPUT ;
    USE SIGNAL ;
    SHAPE ABUTMENT ;
    PORT
      LAYER metal3 ;
      RECT 0.000 723.800 0.140 723.940 ;
    END
  END rd_out[142]
  PIN rd_out[143]
    DIRECTION OUTPUT ;
    USE SIGNAL ;
    SHAPE ABUTMENT ;
    PORT
      LAYER metal3 ;
      RECT 0.000 725.200 0.140 725.340 ;
    END
  END rd_out[143]
  PIN rd_out[144]
    DIRECTION OUTPUT ;
    USE SIGNAL ;
    SHAPE ABUTMENT ;
    PORT
      LAYER metal3 ;
      RECT 0.000 726.600 0.140 726.740 ;
    END
  END rd_out[144]
  PIN rd_out[145]
    DIRECTION OUTPUT ;
    USE SIGNAL ;
    SHAPE ABUTMENT ;
    PORT
      LAYER metal3 ;
      RECT 0.000 728.000 0.140 728.140 ;
    END
  END rd_out[145]
  PIN rd_out[146]
    DIRECTION OUTPUT ;
    USE SIGNAL ;
    SHAPE ABUTMENT ;
    PORT
      LAYER metal3 ;
      RECT 0.000 729.400 0.140 729.540 ;
    END
  END rd_out[146]
  PIN rd_out[147]
    DIRECTION OUTPUT ;
    USE SIGNAL ;
    SHAPE ABUTMENT ;
    PORT
      LAYER metal3 ;
      RECT 0.000 730.800 0.140 730.940 ;
    END
  END rd_out[147]
  PIN rd_out[148]
    DIRECTION OUTPUT ;
    USE SIGNAL ;
    SHAPE ABUTMENT ;
    PORT
      LAYER metal3 ;
      RECT 0.000 732.200 0.140 732.340 ;
    END
  END rd_out[148]
  PIN rd_out[149]
    DIRECTION OUTPUT ;
    USE SIGNAL ;
    SHAPE ABUTMENT ;
    PORT
      LAYER metal3 ;
      RECT 0.000 733.600 0.140 733.740 ;
    END
  END rd_out[149]
  PIN rd_out[150]
    DIRECTION OUTPUT ;
    USE SIGNAL ;
    SHAPE ABUTMENT ;
    PORT
      LAYER metal3 ;
      RECT 0.000 735.000 0.140 735.140 ;
    END
  END rd_out[150]
  PIN rd_out[151]
    DIRECTION OUTPUT ;
    USE SIGNAL ;
    SHAPE ABUTMENT ;
    PORT
      LAYER metal3 ;
      RECT 0.000 736.400 0.140 736.540 ;
    END
  END rd_out[151]
  PIN rd_out[152]
    DIRECTION OUTPUT ;
    USE SIGNAL ;
    SHAPE ABUTMENT ;
    PORT
      LAYER metal3 ;
      RECT 0.000 737.800 0.140 737.940 ;
    END
  END rd_out[152]
  PIN rd_out[153]
    DIRECTION OUTPUT ;
    USE SIGNAL ;
    SHAPE ABUTMENT ;
    PORT
      LAYER metal3 ;
      RECT 0.000 739.200 0.140 739.340 ;
    END
  END rd_out[153]
  PIN rd_out[154]
    DIRECTION OUTPUT ;
    USE SIGNAL ;
    SHAPE ABUTMENT ;
    PORT
      LAYER metal3 ;
      RECT 0.000 740.600 0.140 740.740 ;
    END
  END rd_out[154]
  PIN rd_out[155]
    DIRECTION OUTPUT ;
    USE SIGNAL ;
    SHAPE ABUTMENT ;
    PORT
      LAYER metal3 ;
      RECT 0.000 742.000 0.140 742.140 ;
    END
  END rd_out[155]
  PIN rd_out[156]
    DIRECTION OUTPUT ;
    USE SIGNAL ;
    SHAPE ABUTMENT ;
    PORT
      LAYER metal3 ;
      RECT 0.000 743.400 0.140 743.540 ;
    END
  END rd_out[156]
  PIN rd_out[157]
    DIRECTION OUTPUT ;
    USE SIGNAL ;
    SHAPE ABUTMENT ;
    PORT
      LAYER metal3 ;
      RECT 0.000 744.800 0.140 744.940 ;
    END
  END rd_out[157]
  PIN rd_out[158]
    DIRECTION OUTPUT ;
    USE SIGNAL ;
    SHAPE ABUTMENT ;
    PORT
      LAYER metal3 ;
      RECT 0.000 746.200 0.140 746.340 ;
    END
  END rd_out[158]
  PIN rd_out[159]
    DIRECTION OUTPUT ;
    USE SIGNAL ;
    SHAPE ABUTMENT ;
    PORT
      LAYER metal3 ;
      RECT 0.000 747.600 0.140 747.740 ;
    END
  END rd_out[159]
  PIN rd_out[160]
    DIRECTION OUTPUT ;
    USE SIGNAL ;
    SHAPE ABUTMENT ;
    PORT
      LAYER metal3 ;
      RECT 0.000 749.000 0.140 749.140 ;
    END
  END rd_out[160]
  PIN rd_out[161]
    DIRECTION OUTPUT ;
    USE SIGNAL ;
    SHAPE ABUTMENT ;
    PORT
      LAYER metal3 ;
      RECT 0.000 750.400 0.140 750.540 ;
    END
  END rd_out[161]
  PIN rd_out[162]
    DIRECTION OUTPUT ;
    USE SIGNAL ;
    SHAPE ABUTMENT ;
    PORT
      LAYER metal3 ;
      RECT 0.000 751.800 0.140 751.940 ;
    END
  END rd_out[162]
  PIN rd_out[163]
    DIRECTION OUTPUT ;
    USE SIGNAL ;
    SHAPE ABUTMENT ;
    PORT
      LAYER metal3 ;
      RECT 0.000 753.200 0.140 753.340 ;
    END
  END rd_out[163]
  PIN rd_out[164]
    DIRECTION OUTPUT ;
    USE SIGNAL ;
    SHAPE ABUTMENT ;
    PORT
      LAYER metal3 ;
      RECT 0.000 754.600 0.140 754.740 ;
    END
  END rd_out[164]
  PIN rd_out[165]
    DIRECTION OUTPUT ;
    USE SIGNAL ;
    SHAPE ABUTMENT ;
    PORT
      LAYER metal3 ;
      RECT 0.000 756.000 0.140 756.140 ;
    END
  END rd_out[165]
  PIN rd_out[166]
    DIRECTION OUTPUT ;
    USE SIGNAL ;
    SHAPE ABUTMENT ;
    PORT
      LAYER metal3 ;
      RECT 0.000 757.400 0.140 757.540 ;
    END
  END rd_out[166]
  PIN rd_out[167]
    DIRECTION OUTPUT ;
    USE SIGNAL ;
    SHAPE ABUTMENT ;
    PORT
      LAYER metal3 ;
      RECT 0.000 758.800 0.140 758.940 ;
    END
  END rd_out[167]
  PIN rd_out[168]
    DIRECTION OUTPUT ;
    USE SIGNAL ;
    SHAPE ABUTMENT ;
    PORT
      LAYER metal3 ;
      RECT 0.000 760.200 0.140 760.340 ;
    END
  END rd_out[168]
  PIN rd_out[169]
    DIRECTION OUTPUT ;
    USE SIGNAL ;
    SHAPE ABUTMENT ;
    PORT
      LAYER metal3 ;
      RECT 0.000 761.600 0.140 761.740 ;
    END
  END rd_out[169]
  PIN rd_out[170]
    DIRECTION OUTPUT ;
    USE SIGNAL ;
    SHAPE ABUTMENT ;
    PORT
      LAYER metal3 ;
      RECT 0.000 763.000 0.140 763.140 ;
    END
  END rd_out[170]
  PIN rd_out[171]
    DIRECTION OUTPUT ;
    USE SIGNAL ;
    SHAPE ABUTMENT ;
    PORT
      LAYER metal3 ;
      RECT 0.000 764.400 0.140 764.540 ;
    END
  END rd_out[171]
  PIN rd_out[172]
    DIRECTION OUTPUT ;
    USE SIGNAL ;
    SHAPE ABUTMENT ;
    PORT
      LAYER metal3 ;
      RECT 0.000 765.800 0.140 765.940 ;
    END
  END rd_out[172]
  PIN rd_out[173]
    DIRECTION OUTPUT ;
    USE SIGNAL ;
    SHAPE ABUTMENT ;
    PORT
      LAYER metal3 ;
      RECT 0.000 767.200 0.140 767.340 ;
    END
  END rd_out[173]
  PIN rd_out[174]
    DIRECTION OUTPUT ;
    USE SIGNAL ;
    SHAPE ABUTMENT ;
    PORT
      LAYER metal3 ;
      RECT 0.000 768.600 0.140 768.740 ;
    END
  END rd_out[174]
  PIN rd_out[175]
    DIRECTION OUTPUT ;
    USE SIGNAL ;
    SHAPE ABUTMENT ;
    PORT
      LAYER metal3 ;
      RECT 0.000 770.000 0.140 770.140 ;
    END
  END rd_out[175]
  PIN rd_out[176]
    DIRECTION OUTPUT ;
    USE SIGNAL ;
    SHAPE ABUTMENT ;
    PORT
      LAYER metal3 ;
      RECT 0.000 771.400 0.140 771.540 ;
    END
  END rd_out[176]
  PIN rd_out[177]
    DIRECTION OUTPUT ;
    USE SIGNAL ;
    SHAPE ABUTMENT ;
    PORT
      LAYER metal3 ;
      RECT 0.000 772.800 0.140 772.940 ;
    END
  END rd_out[177]
  PIN rd_out[178]
    DIRECTION OUTPUT ;
    USE SIGNAL ;
    SHAPE ABUTMENT ;
    PORT
      LAYER metal3 ;
      RECT 0.000 774.200 0.140 774.340 ;
    END
  END rd_out[178]
  PIN rd_out[179]
    DIRECTION OUTPUT ;
    USE SIGNAL ;
    SHAPE ABUTMENT ;
    PORT
      LAYER metal3 ;
      RECT 0.000 775.600 0.140 775.740 ;
    END
  END rd_out[179]
  PIN rd_out[180]
    DIRECTION OUTPUT ;
    USE SIGNAL ;
    SHAPE ABUTMENT ;
    PORT
      LAYER metal3 ;
      RECT 0.000 777.000 0.140 777.140 ;
    END
  END rd_out[180]
  PIN rd_out[181]
    DIRECTION OUTPUT ;
    USE SIGNAL ;
    SHAPE ABUTMENT ;
    PORT
      LAYER metal3 ;
      RECT 0.000 778.400 0.140 778.540 ;
    END
  END rd_out[181]
  PIN rd_out[182]
    DIRECTION OUTPUT ;
    USE SIGNAL ;
    SHAPE ABUTMENT ;
    PORT
      LAYER metal3 ;
      RECT 0.000 779.800 0.140 779.940 ;
    END
  END rd_out[182]
  PIN rd_out[183]
    DIRECTION OUTPUT ;
    USE SIGNAL ;
    SHAPE ABUTMENT ;
    PORT
      LAYER metal3 ;
      RECT 0.000 781.200 0.140 781.340 ;
    END
  END rd_out[183]
  PIN clk
    DIRECTION INPUT ;
    USE SIGNAL ;
    SHAPE ABUTMENT ;
    PORT
      LAYER metal3 ;
      RECT 0.000 782.600 0.140 782.740 ;
    END
  END clk
  PIN ce_in
    DIRECTION INPUT ;
    USE SIGNAL ;
    SHAPE ABUTMENT ;
    PORT
      LAYER metal3 ;
      RECT 0.000 784.000 0.140 784.140 ;
    END
  END ce_in
  PIN we_in
    DIRECTION INPUT ;
    USE SIGNAL ;
    SHAPE ABUTMENT ;
    PORT
      LAYER metal3 ;
      RECT 0.000 785.400 0.140 785.540 ;
    END
  END we_in
  OBS
    LAYER metal1 ;
      RECT 0.000 0.000 299.250 791.000 ;
    LAYER metal2 ;
      RECT 0.000 0.000 299.250 791.000 ;
    LAYER metal3 ;
      RECT 0.000 0.000 299.250 791.000 ;
    LAYER metal4 ;
      RECT 0.000 0.000 299.250 791.000 ;
  END
END fakeram_64x184_1rw
END LIBRARY
